VERSION 5.8 ;
BUSBITCHARS "[]" ;
DIVIDERCHAR "/" ;
UNITS
    DATABASE MICRONS 1000 ;
END UNITS

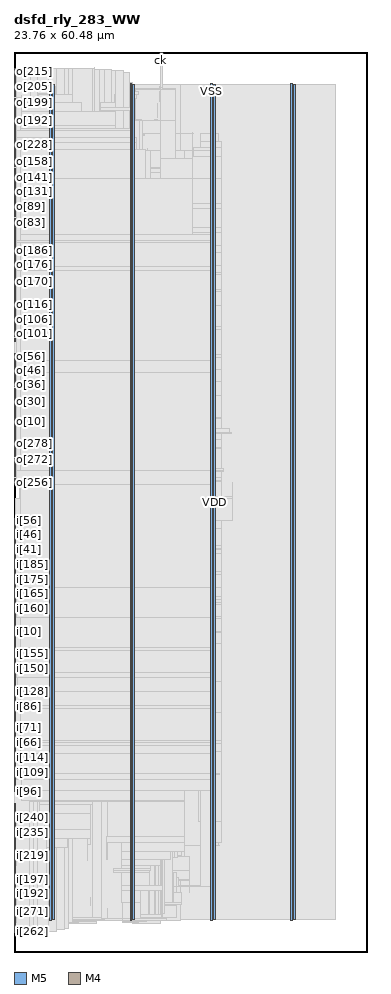
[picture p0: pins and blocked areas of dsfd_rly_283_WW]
MACRO dsfd_rly_283_WW
  FOREIGN dsfd_rly_283_WW 0 0 ;
  CLASS BLOCK ;
  SIZE 23.76 BY 60.48 ;
  PIN ck
    DIRECTION INPUT ;
    USE SIGNAL ;
    PORT
      LAYER M5 ;
        RECT  9.84 60.396 9.864 60.48 ;
    END
  END ck
  PIN i[0]
    DIRECTION INPUT ;
    USE SIGNAL ;
    PORT
      LAYER M4 ;
        RECT  0 20.016 0.084 20.04 ;
    END
  END i[0]
  PIN i[100]
    DIRECTION INPUT ;
    USE SIGNAL ;
    PORT
      LAYER M4 ;
        RECT  0 11.184 0.084 11.208 ;
    END
  END i[100]
  PIN i[101]
    DIRECTION INPUT ;
    USE SIGNAL ;
    PORT
      LAYER M4 ;
        RECT  0 11.28 0.084 11.304 ;
    END
  END i[101]
  PIN i[102]
    DIRECTION INPUT ;
    USE SIGNAL ;
    PORT
      LAYER M4 ;
        RECT  0 11.376 0.084 11.4 ;
    END
  END i[102]
  PIN i[103]
    DIRECTION INPUT ;
    USE SIGNAL ;
    PORT
      LAYER M4 ;
        RECT  0 11.472 0.084 11.496 ;
    END
  END i[103]
  PIN i[104]
    DIRECTION INPUT ;
    USE SIGNAL ;
    PORT
      LAYER M4 ;
        RECT  0 11.568 0.084 11.592 ;
    END
  END i[104]
  PIN i[105]
    DIRECTION INPUT ;
    USE SIGNAL ;
    PORT
      LAYER M4 ;
        RECT  0 11.664 0.084 11.688 ;
    END
  END i[105]
  PIN i[106]
    DIRECTION INPUT ;
    USE SIGNAL ;
    PORT
      LAYER M4 ;
        RECT  0 11.76 0.084 11.784 ;
    END
  END i[106]
  PIN i[107]
    DIRECTION INPUT ;
    USE SIGNAL ;
    PORT
      LAYER M4 ;
        RECT  0 11.856 0.084 11.88 ;
    END
  END i[107]
  PIN i[108]
    DIRECTION INPUT ;
    USE SIGNAL ;
    PORT
      LAYER M4 ;
        RECT  0 11.952 0.084 11.976 ;
    END
  END i[108]
  PIN i[109]
    DIRECTION INPUT ;
    USE SIGNAL ;
    PORT
      LAYER M4 ;
        RECT  0 12.048 0.084 12.072 ;
    END
  END i[109]
  PIN i[10]
    DIRECTION INPUT ;
    USE SIGNAL ;
    PORT
      LAYER M4 ;
        RECT  0 20.976 0.084 21 ;
    END
  END i[10]
  PIN i[110]
    DIRECTION INPUT ;
    USE SIGNAL ;
    PORT
      LAYER M4 ;
        RECT  0 12.144 0.084 12.168 ;
    END
  END i[110]
  PIN i[111]
    DIRECTION INPUT ;
    USE SIGNAL ;
    PORT
      LAYER M4 ;
        RECT  0 12.24 0.084 12.264 ;
    END
  END i[111]
  PIN i[112]
    DIRECTION INPUT ;
    USE SIGNAL ;
    PORT
      LAYER M4 ;
        RECT  0 12.336 0.084 12.36 ;
    END
  END i[112]
  PIN i[113]
    DIRECTION INPUT ;
    USE SIGNAL ;
    PORT
      LAYER M4 ;
        RECT  0 12.432 0.084 12.456 ;
    END
  END i[113]
  PIN i[114]
    DIRECTION INPUT ;
    USE SIGNAL ;
    PORT
      LAYER M4 ;
        RECT  0 12.528 0.084 12.552 ;
    END
  END i[114]
  PIN i[115]
    DIRECTION INPUT ;
    USE SIGNAL ;
    PORT
      LAYER M4 ;
        RECT  0 12.624 0.084 12.648 ;
    END
  END i[115]
  PIN i[116]
    DIRECTION INPUT ;
    USE SIGNAL ;
    PORT
      LAYER M4 ;
        RECT  0 12.72 0.084 12.744 ;
    END
  END i[116]
  PIN i[117]
    DIRECTION INPUT ;
    USE SIGNAL ;
    PORT
      LAYER M4 ;
        RECT  0 12.816 0.084 12.84 ;
    END
  END i[117]
  PIN i[118]
    DIRECTION INPUT ;
    USE SIGNAL ;
    PORT
      LAYER M4 ;
        RECT  0 12.912 0.084 12.936 ;
    END
  END i[118]
  PIN i[119]
    DIRECTION INPUT ;
    USE SIGNAL ;
    PORT
      LAYER M4 ;
        RECT  0 13.008 0.084 13.032 ;
    END
  END i[119]
  PIN i[11]
    DIRECTION INPUT ;
    USE SIGNAL ;
    PORT
      LAYER M4 ;
        RECT  0 21.072 0.084 21.096 ;
    END
  END i[11]
  PIN i[120]
    DIRECTION INPUT ;
    USE SIGNAL ;
    PORT
      LAYER M4 ;
        RECT  0 13.104 0.084 13.128 ;
    END
  END i[120]
  PIN i[121]
    DIRECTION INPUT ;
    USE SIGNAL ;
    PORT
      LAYER M4 ;
        RECT  0 13.2 0.084 13.224 ;
    END
  END i[121]
  PIN i[122]
    DIRECTION INPUT ;
    USE SIGNAL ;
    PORT
      LAYER M4 ;
        RECT  0 13.296 0.084 13.32 ;
    END
  END i[122]
  PIN i[123]
    DIRECTION INPUT ;
    USE SIGNAL ;
    PORT
      LAYER M4 ;
        RECT  0 13.392 0.084 13.416 ;
    END
  END i[123]
  PIN i[124]
    DIRECTION INPUT ;
    USE SIGNAL ;
    PORT
      LAYER M4 ;
        RECT  0 13.488 0.084 13.512 ;
    END
  END i[124]
  PIN i[125]
    DIRECTION INPUT ;
    USE SIGNAL ;
    PORT
      LAYER M4 ;
        RECT  0 13.584 0.084 13.608 ;
    END
  END i[125]
  PIN i[126]
    DIRECTION INPUT ;
    USE SIGNAL ;
    PORT
      LAYER M4 ;
        RECT  0 13.68 0.084 13.704 ;
    END
  END i[126]
  PIN i[127]
    DIRECTION INPUT ;
    USE SIGNAL ;
    PORT
      LAYER M4 ;
        RECT  0 13.776 0.084 13.8 ;
    END
  END i[127]
  PIN i[128]
    DIRECTION INPUT ;
    USE SIGNAL ;
    PORT
      LAYER M4 ;
        RECT  0 16.944 0.084 16.968 ;
    END
  END i[128]
  PIN i[129]
    DIRECTION INPUT ;
    USE SIGNAL ;
    PORT
      LAYER M4 ;
        RECT  0 17.04 0.084 17.064 ;
    END
  END i[129]
  PIN i[12]
    DIRECTION INPUT ;
    USE SIGNAL ;
    PORT
      LAYER M4 ;
        RECT  0 21.168 0.084 21.192 ;
    END
  END i[12]
  PIN i[130]
    DIRECTION INPUT ;
    USE SIGNAL ;
    PORT
      LAYER M4 ;
        RECT  0 17.136 0.084 17.16 ;
    END
  END i[130]
  PIN i[131]
    DIRECTION INPUT ;
    USE SIGNAL ;
    PORT
      LAYER M4 ;
        RECT  0 17.232 0.084 17.256 ;
    END
  END i[131]
  PIN i[132]
    DIRECTION INPUT ;
    USE SIGNAL ;
    PORT
      LAYER M4 ;
        RECT  0 17.328 0.084 17.352 ;
    END
  END i[132]
  PIN i[133]
    DIRECTION INPUT ;
    USE SIGNAL ;
    PORT
      LAYER M4 ;
        RECT  0 17.424 0.084 17.448 ;
    END
  END i[133]
  PIN i[134]
    DIRECTION INPUT ;
    USE SIGNAL ;
    PORT
      LAYER M4 ;
        RECT  0 17.52 0.084 17.544 ;
    END
  END i[134]
  PIN i[135]
    DIRECTION INPUT ;
    USE SIGNAL ;
    PORT
      LAYER M4 ;
        RECT  0 17.616 0.084 17.64 ;
    END
  END i[135]
  PIN i[136]
    DIRECTION INPUT ;
    USE SIGNAL ;
    PORT
      LAYER M4 ;
        RECT  0 17.712 0.084 17.736 ;
    END
  END i[136]
  PIN i[137]
    DIRECTION INPUT ;
    USE SIGNAL ;
    PORT
      LAYER M4 ;
        RECT  0 17.808 0.084 17.832 ;
    END
  END i[137]
  PIN i[138]
    DIRECTION INPUT ;
    USE SIGNAL ;
    PORT
      LAYER M4 ;
        RECT  0 17.904 0.084 17.928 ;
    END
  END i[138]
  PIN i[139]
    DIRECTION INPUT ;
    USE SIGNAL ;
    PORT
      LAYER M4 ;
        RECT  0 18 0.084 18.024 ;
    END
  END i[139]
  PIN i[13]
    DIRECTION INPUT ;
    USE SIGNAL ;
    PORT
      LAYER M4 ;
        RECT  0 21.264 0.084 21.288 ;
    END
  END i[13]
  PIN i[140]
    DIRECTION INPUT ;
    USE SIGNAL ;
    PORT
      LAYER M4 ;
        RECT  0 18.096 0.084 18.12 ;
    END
  END i[140]
  PIN i[141]
    DIRECTION INPUT ;
    USE SIGNAL ;
    PORT
      LAYER M4 ;
        RECT  0 18.192 0.084 18.216 ;
    END
  END i[141]
  PIN i[142]
    DIRECTION INPUT ;
    USE SIGNAL ;
    PORT
      LAYER M4 ;
        RECT  0 18.288 0.084 18.312 ;
    END
  END i[142]
  PIN i[143]
    DIRECTION INPUT ;
    USE SIGNAL ;
    PORT
      LAYER M4 ;
        RECT  0 18.384 0.084 18.408 ;
    END
  END i[143]
  PIN i[144]
    DIRECTION INPUT ;
    USE SIGNAL ;
    PORT
      LAYER M4 ;
        RECT  0 18.48 0.084 18.504 ;
    END
  END i[144]
  PIN i[145]
    DIRECTION INPUT ;
    USE SIGNAL ;
    PORT
      LAYER M4 ;
        RECT  0 18.576 0.084 18.6 ;
    END
  END i[145]
  PIN i[146]
    DIRECTION INPUT ;
    USE SIGNAL ;
    PORT
      LAYER M4 ;
        RECT  0 18.672 0.084 18.696 ;
    END
  END i[146]
  PIN i[147]
    DIRECTION INPUT ;
    USE SIGNAL ;
    PORT
      LAYER M4 ;
        RECT  0 18.768 0.084 18.792 ;
    END
  END i[147]
  PIN i[148]
    DIRECTION INPUT ;
    USE SIGNAL ;
    PORT
      LAYER M4 ;
        RECT  0 18.864 0.084 18.888 ;
    END
  END i[148]
  PIN i[149]
    DIRECTION INPUT ;
    USE SIGNAL ;
    PORT
      LAYER M4 ;
        RECT  0 18.96 0.084 18.984 ;
    END
  END i[149]
  PIN i[14]
    DIRECTION INPUT ;
    USE SIGNAL ;
    PORT
      LAYER M4 ;
        RECT  0 21.36 0.084 21.384 ;
    END
  END i[14]
  PIN i[150]
    DIRECTION INPUT ;
    USE SIGNAL ;
    PORT
      LAYER M4 ;
        RECT  0 19.056 0.084 19.08 ;
    END
  END i[150]
  PIN i[151]
    DIRECTION INPUT ;
    USE SIGNAL ;
    PORT
      LAYER M4 ;
        RECT  0 19.152 0.084 19.176 ;
    END
  END i[151]
  PIN i[152]
    DIRECTION INPUT ;
    USE SIGNAL ;
    PORT
      LAYER M4 ;
        RECT  0 19.248 0.084 19.272 ;
    END
  END i[152]
  PIN i[153]
    DIRECTION INPUT ;
    USE SIGNAL ;
    PORT
      LAYER M4 ;
        RECT  0 19.344 0.084 19.368 ;
    END
  END i[153]
  PIN i[154]
    DIRECTION INPUT ;
    USE SIGNAL ;
    PORT
      LAYER M4 ;
        RECT  0 19.44 0.084 19.464 ;
    END
  END i[154]
  PIN i[155]
    DIRECTION INPUT ;
    USE SIGNAL ;
    PORT
      LAYER M4 ;
        RECT  0 19.536 0.084 19.56 ;
    END
  END i[155]
  PIN i[156]
    DIRECTION INPUT ;
    USE SIGNAL ;
    PORT
      LAYER M4 ;
        RECT  0 19.632 0.084 19.656 ;
    END
  END i[156]
  PIN i[157]
    DIRECTION INPUT ;
    USE SIGNAL ;
    PORT
      LAYER M4 ;
        RECT  0 19.728 0.084 19.752 ;
    END
  END i[157]
  PIN i[158]
    DIRECTION INPUT ;
    USE SIGNAL ;
    PORT
      LAYER M4 ;
        RECT  0 19.824 0.084 19.848 ;
    END
  END i[158]
  PIN i[159]
    DIRECTION INPUT ;
    USE SIGNAL ;
    PORT
      LAYER M4 ;
        RECT  0 19.92 0.084 19.944 ;
    END
  END i[159]
  PIN i[15]
    DIRECTION INPUT ;
    USE SIGNAL ;
    PORT
      LAYER M4 ;
        RECT  0 21.456 0.084 21.48 ;
    END
  END i[15]
  PIN i[160]
    DIRECTION INPUT ;
    USE SIGNAL ;
    PORT
      LAYER M4 ;
        RECT  0 23.088 0.084 23.112 ;
    END
  END i[160]
  PIN i[161]
    DIRECTION INPUT ;
    USE SIGNAL ;
    PORT
      LAYER M4 ;
        RECT  0 23.184 0.084 23.208 ;
    END
  END i[161]
  PIN i[162]
    DIRECTION INPUT ;
    USE SIGNAL ;
    PORT
      LAYER M4 ;
        RECT  0 23.28 0.084 23.304 ;
    END
  END i[162]
  PIN i[163]
    DIRECTION INPUT ;
    USE SIGNAL ;
    PORT
      LAYER M4 ;
        RECT  0 23.376 0.084 23.4 ;
    END
  END i[163]
  PIN i[164]
    DIRECTION INPUT ;
    USE SIGNAL ;
    PORT
      LAYER M4 ;
        RECT  0 23.472 0.084 23.496 ;
    END
  END i[164]
  PIN i[165]
    DIRECTION INPUT ;
    USE SIGNAL ;
    PORT
      LAYER M4 ;
        RECT  0 23.568 0.084 23.592 ;
    END
  END i[165]
  PIN i[166]
    DIRECTION INPUT ;
    USE SIGNAL ;
    PORT
      LAYER M4 ;
        RECT  0 23.664 0.084 23.688 ;
    END
  END i[166]
  PIN i[167]
    DIRECTION INPUT ;
    USE SIGNAL ;
    PORT
      LAYER M4 ;
        RECT  0 23.76 0.084 23.784 ;
    END
  END i[167]
  PIN i[168]
    DIRECTION INPUT ;
    USE SIGNAL ;
    PORT
      LAYER M4 ;
        RECT  0 23.856 0.084 23.88 ;
    END
  END i[168]
  PIN i[169]
    DIRECTION INPUT ;
    USE SIGNAL ;
    PORT
      LAYER M4 ;
        RECT  0 23.952 0.084 23.976 ;
    END
  END i[169]
  PIN i[16]
    DIRECTION INPUT ;
    USE SIGNAL ;
    PORT
      LAYER M4 ;
        RECT  0 21.552 0.084 21.576 ;
    END
  END i[16]
  PIN i[170]
    DIRECTION INPUT ;
    USE SIGNAL ;
    PORT
      LAYER M4 ;
        RECT  0 24.048 0.084 24.072 ;
    END
  END i[170]
  PIN i[171]
    DIRECTION INPUT ;
    USE SIGNAL ;
    PORT
      LAYER M4 ;
        RECT  0 24.144 0.084 24.168 ;
    END
  END i[171]
  PIN i[172]
    DIRECTION INPUT ;
    USE SIGNAL ;
    PORT
      LAYER M4 ;
        RECT  0 24.24 0.084 24.264 ;
    END
  END i[172]
  PIN i[173]
    DIRECTION INPUT ;
    USE SIGNAL ;
    PORT
      LAYER M4 ;
        RECT  0 24.336 0.084 24.36 ;
    END
  END i[173]
  PIN i[174]
    DIRECTION INPUT ;
    USE SIGNAL ;
    PORT
      LAYER M4 ;
        RECT  0 24.432 0.084 24.456 ;
    END
  END i[174]
  PIN i[175]
    DIRECTION INPUT ;
    USE SIGNAL ;
    PORT
      LAYER M4 ;
        RECT  0 24.528 0.084 24.552 ;
    END
  END i[175]
  PIN i[176]
    DIRECTION INPUT ;
    USE SIGNAL ;
    PORT
      LAYER M4 ;
        RECT  0 24.624 0.084 24.648 ;
    END
  END i[176]
  PIN i[177]
    DIRECTION INPUT ;
    USE SIGNAL ;
    PORT
      LAYER M4 ;
        RECT  0 24.72 0.084 24.744 ;
    END
  END i[177]
  PIN i[178]
    DIRECTION INPUT ;
    USE SIGNAL ;
    PORT
      LAYER M4 ;
        RECT  0 24.816 0.084 24.84 ;
    END
  END i[178]
  PIN i[179]
    DIRECTION INPUT ;
    USE SIGNAL ;
    PORT
      LAYER M4 ;
        RECT  0 24.912 0.084 24.936 ;
    END
  END i[179]
  PIN i[17]
    DIRECTION INPUT ;
    USE SIGNAL ;
    PORT
      LAYER M4 ;
        RECT  0 21.648 0.084 21.672 ;
    END
  END i[17]
  PIN i[180]
    DIRECTION INPUT ;
    USE SIGNAL ;
    PORT
      LAYER M4 ;
        RECT  0 25.008 0.084 25.032 ;
    END
  END i[180]
  PIN i[181]
    DIRECTION INPUT ;
    USE SIGNAL ;
    PORT
      LAYER M4 ;
        RECT  0 25.104 0.084 25.128 ;
    END
  END i[181]
  PIN i[182]
    DIRECTION INPUT ;
    USE SIGNAL ;
    PORT
      LAYER M4 ;
        RECT  0 25.2 0.084 25.224 ;
    END
  END i[182]
  PIN i[183]
    DIRECTION INPUT ;
    USE SIGNAL ;
    PORT
      LAYER M4 ;
        RECT  0 25.296 0.084 25.32 ;
    END
  END i[183]
  PIN i[184]
    DIRECTION INPUT ;
    USE SIGNAL ;
    PORT
      LAYER M4 ;
        RECT  0 25.392 0.084 25.416 ;
    END
  END i[184]
  PIN i[185]
    DIRECTION INPUT ;
    USE SIGNAL ;
    PORT
      LAYER M4 ;
        RECT  0 25.488 0.084 25.512 ;
    END
  END i[185]
  PIN i[186]
    DIRECTION INPUT ;
    USE SIGNAL ;
    PORT
      LAYER M4 ;
        RECT  0 25.584 0.084 25.608 ;
    END
  END i[186]
  PIN i[187]
    DIRECTION INPUT ;
    USE SIGNAL ;
    PORT
      LAYER M4 ;
        RECT  0 25.68 0.084 25.704 ;
    END
  END i[187]
  PIN i[188]
    DIRECTION INPUT ;
    USE SIGNAL ;
    PORT
      LAYER M4 ;
        RECT  0 25.776 0.084 25.8 ;
    END
  END i[188]
  PIN i[189]
    DIRECTION INPUT ;
    USE SIGNAL ;
    PORT
      LAYER M4 ;
        RECT  0 25.872 0.084 25.896 ;
    END
  END i[189]
  PIN i[18]
    DIRECTION INPUT ;
    USE SIGNAL ;
    PORT
      LAYER M4 ;
        RECT  0 21.744 0.084 21.768 ;
    END
  END i[18]
  PIN i[190]
    DIRECTION INPUT ;
    USE SIGNAL ;
    PORT
      LAYER M4 ;
        RECT  0 25.968 0.084 25.992 ;
    END
  END i[190]
  PIN i[191]
    DIRECTION INPUT ;
    USE SIGNAL ;
    PORT
      LAYER M4 ;
        RECT  0 26.064 0.084 26.088 ;
    END
  END i[191]
  PIN i[192]
    DIRECTION INPUT ;
    USE SIGNAL ;
    PORT
      LAYER M4 ;
        RECT  0 3.888 0.084 3.912 ;
    END
  END i[192]
  PIN i[193]
    DIRECTION INPUT ;
    USE SIGNAL ;
    PORT
      LAYER M4 ;
        RECT  0 3.984 0.084 4.008 ;
    END
  END i[193]
  PIN i[194]
    DIRECTION INPUT ;
    USE SIGNAL ;
    PORT
      LAYER M4 ;
        RECT  0 4.08 0.084 4.104 ;
    END
  END i[194]
  PIN i[195]
    DIRECTION INPUT ;
    USE SIGNAL ;
    PORT
      LAYER M4 ;
        RECT  0 4.176 0.084 4.2 ;
    END
  END i[195]
  PIN i[196]
    DIRECTION INPUT ;
    USE SIGNAL ;
    PORT
      LAYER M4 ;
        RECT  0 4.272 0.084 4.296 ;
    END
  END i[196]
  PIN i[197]
    DIRECTION INPUT ;
    USE SIGNAL ;
    PORT
      LAYER M4 ;
        RECT  0 4.368 0.084 4.392 ;
    END
  END i[197]
  PIN i[198]
    DIRECTION INPUT ;
    USE SIGNAL ;
    PORT
      LAYER M4 ;
        RECT  0 4.464 0.084 4.488 ;
    END
  END i[198]
  PIN i[199]
    DIRECTION INPUT ;
    USE SIGNAL ;
    PORT
      LAYER M4 ;
        RECT  0 4.56 0.084 4.584 ;
    END
  END i[199]
  PIN i[19]
    DIRECTION INPUT ;
    USE SIGNAL ;
    PORT
      LAYER M4 ;
        RECT  0 21.84 0.084 21.864 ;
    END
  END i[19]
  PIN i[1]
    DIRECTION INPUT ;
    USE SIGNAL ;
    PORT
      LAYER M4 ;
        RECT  0 20.112 0.084 20.136 ;
    END
  END i[1]
  PIN i[200]
    DIRECTION INPUT ;
    USE SIGNAL ;
    PORT
      LAYER M4 ;
        RECT  0 4.656 0.084 4.68 ;
    END
  END i[200]
  PIN i[201]
    DIRECTION INPUT ;
    USE SIGNAL ;
    PORT
      LAYER M4 ;
        RECT  0 4.752 0.084 4.776 ;
    END
  END i[201]
  PIN i[202]
    DIRECTION INPUT ;
    USE SIGNAL ;
    PORT
      LAYER M4 ;
        RECT  0 4.848 0.084 4.872 ;
    END
  END i[202]
  PIN i[203]
    DIRECTION INPUT ;
    USE SIGNAL ;
    PORT
      LAYER M4 ;
        RECT  0 4.944 0.084 4.968 ;
    END
  END i[203]
  PIN i[204]
    DIRECTION INPUT ;
    USE SIGNAL ;
    PORT
      LAYER M4 ;
        RECT  0 5.04 0.084 5.064 ;
    END
  END i[204]
  PIN i[205]
    DIRECTION INPUT ;
    USE SIGNAL ;
    PORT
      LAYER M4 ;
        RECT  0 5.136 0.084 5.16 ;
    END
  END i[205]
  PIN i[206]
    DIRECTION INPUT ;
    USE SIGNAL ;
    PORT
      LAYER M4 ;
        RECT  0 5.232 0.084 5.256 ;
    END
  END i[206]
  PIN i[207]
    DIRECTION INPUT ;
    USE SIGNAL ;
    PORT
      LAYER M4 ;
        RECT  0 5.328 0.084 5.352 ;
    END
  END i[207]
  PIN i[208]
    DIRECTION INPUT ;
    USE SIGNAL ;
    PORT
      LAYER M4 ;
        RECT  0 5.424 0.084 5.448 ;
    END
  END i[208]
  PIN i[209]
    DIRECTION INPUT ;
    USE SIGNAL ;
    PORT
      LAYER M4 ;
        RECT  0 5.52 0.084 5.544 ;
    END
  END i[209]
  PIN i[20]
    DIRECTION INPUT ;
    USE SIGNAL ;
    PORT
      LAYER M4 ;
        RECT  0 21.936 0.084 21.96 ;
    END
  END i[20]
  PIN i[210]
    DIRECTION INPUT ;
    USE SIGNAL ;
    PORT
      LAYER M4 ;
        RECT  0 5.616 0.084 5.64 ;
    END
  END i[210]
  PIN i[211]
    DIRECTION INPUT ;
    USE SIGNAL ;
    PORT
      LAYER M4 ;
        RECT  0 5.712 0.084 5.736 ;
    END
  END i[211]
  PIN i[212]
    DIRECTION INPUT ;
    USE SIGNAL ;
    PORT
      LAYER M4 ;
        RECT  0 5.808 0.084 5.832 ;
    END
  END i[212]
  PIN i[213]
    DIRECTION INPUT ;
    USE SIGNAL ;
    PORT
      LAYER M4 ;
        RECT  0 5.904 0.084 5.928 ;
    END
  END i[213]
  PIN i[214]
    DIRECTION INPUT ;
    USE SIGNAL ;
    PORT
      LAYER M4 ;
        RECT  0 6 0.084 6.024 ;
    END
  END i[214]
  PIN i[215]
    DIRECTION INPUT ;
    USE SIGNAL ;
    PORT
      LAYER M4 ;
        RECT  0 6.096 0.084 6.12 ;
    END
  END i[215]
  PIN i[216]
    DIRECTION INPUT ;
    USE SIGNAL ;
    PORT
      LAYER M4 ;
        RECT  0 6.192 0.084 6.216 ;
    END
  END i[216]
  PIN i[217]
    DIRECTION INPUT ;
    USE SIGNAL ;
    PORT
      LAYER M4 ;
        RECT  0 6.288 0.084 6.312 ;
    END
  END i[217]
  PIN i[218]
    DIRECTION INPUT ;
    USE SIGNAL ;
    PORT
      LAYER M4 ;
        RECT  0 6.384 0.084 6.408 ;
    END
  END i[218]
  PIN i[219]
    DIRECTION INPUT ;
    USE SIGNAL ;
    PORT
      LAYER M4 ;
        RECT  0 6.48 0.084 6.504 ;
    END
  END i[219]
  PIN i[21]
    DIRECTION INPUT ;
    USE SIGNAL ;
    PORT
      LAYER M4 ;
        RECT  0 22.032 0.084 22.056 ;
    END
  END i[21]
  PIN i[220]
    DIRECTION INPUT ;
    USE SIGNAL ;
    PORT
      LAYER M4 ;
        RECT  0 6.576 0.084 6.6 ;
    END
  END i[220]
  PIN i[221]
    DIRECTION INPUT ;
    USE SIGNAL ;
    PORT
      LAYER M4 ;
        RECT  0 6.672 0.084 6.696 ;
    END
  END i[221]
  PIN i[222]
    DIRECTION INPUT ;
    USE SIGNAL ;
    PORT
      LAYER M4 ;
        RECT  0 6.768 0.084 6.792 ;
    END
  END i[222]
  PIN i[223]
    DIRECTION INPUT ;
    USE SIGNAL ;
    PORT
      LAYER M4 ;
        RECT  0 6.864 0.084 6.888 ;
    END
  END i[223]
  PIN i[224]
    DIRECTION INPUT ;
    USE SIGNAL ;
    PORT
      LAYER M4 ;
        RECT  0 6.96 0.084 6.984 ;
    END
  END i[224]
  PIN i[225]
    DIRECTION INPUT ;
    USE SIGNAL ;
    PORT
      LAYER M4 ;
        RECT  0 7.056 0.084 7.08 ;
    END
  END i[225]
  PIN i[226]
    DIRECTION INPUT ;
    USE SIGNAL ;
    PORT
      LAYER M4 ;
        RECT  0 7.152 0.084 7.176 ;
    END
  END i[226]
  PIN i[227]
    DIRECTION INPUT ;
    USE SIGNAL ;
    PORT
      LAYER M4 ;
        RECT  0 7.248 0.084 7.272 ;
    END
  END i[227]
  PIN i[228]
    DIRECTION INPUT ;
    USE SIGNAL ;
    PORT
      LAYER M4 ;
        RECT  0 7.344 0.084 7.368 ;
    END
  END i[228]
  PIN i[229]
    DIRECTION INPUT ;
    USE SIGNAL ;
    PORT
      LAYER M4 ;
        RECT  0 7.44 0.084 7.464 ;
    END
  END i[229]
  PIN i[22]
    DIRECTION INPUT ;
    USE SIGNAL ;
    PORT
      LAYER M4 ;
        RECT  0 22.128 0.084 22.152 ;
    END
  END i[22]
  PIN i[230]
    DIRECTION INPUT ;
    USE SIGNAL ;
    PORT
      LAYER M4 ;
        RECT  0 7.536 0.084 7.56 ;
    END
  END i[230]
  PIN i[231]
    DIRECTION INPUT ;
    USE SIGNAL ;
    PORT
      LAYER M4 ;
        RECT  0 7.632 0.084 7.656 ;
    END
  END i[231]
  PIN i[232]
    DIRECTION INPUT ;
    USE SIGNAL ;
    PORT
      LAYER M4 ;
        RECT  0 7.728 0.084 7.752 ;
    END
  END i[232]
  PIN i[233]
    DIRECTION INPUT ;
    USE SIGNAL ;
    PORT
      LAYER M4 ;
        RECT  0 7.824 0.084 7.848 ;
    END
  END i[233]
  PIN i[234]
    DIRECTION INPUT ;
    USE SIGNAL ;
    PORT
      LAYER M4 ;
        RECT  0 7.92 0.084 7.944 ;
    END
  END i[234]
  PIN i[235]
    DIRECTION INPUT ;
    USE SIGNAL ;
    PORT
      LAYER M4 ;
        RECT  0 8.016 0.084 8.04 ;
    END
  END i[235]
  PIN i[236]
    DIRECTION INPUT ;
    USE SIGNAL ;
    PORT
      LAYER M4 ;
        RECT  0 8.112 0.084 8.136 ;
    END
  END i[236]
  PIN i[237]
    DIRECTION INPUT ;
    USE SIGNAL ;
    PORT
      LAYER M4 ;
        RECT  0 8.208 0.084 8.232 ;
    END
  END i[237]
  PIN i[238]
    DIRECTION INPUT ;
    USE SIGNAL ;
    PORT
      LAYER M4 ;
        RECT  0 8.304 0.084 8.328 ;
    END
  END i[238]
  PIN i[239]
    DIRECTION INPUT ;
    USE SIGNAL ;
    PORT
      LAYER M4 ;
        RECT  0 8.4 0.084 8.424 ;
    END
  END i[239]
  PIN i[23]
    DIRECTION INPUT ;
    USE SIGNAL ;
    PORT
      LAYER M4 ;
        RECT  0 22.224 0.084 22.248 ;
    END
  END i[23]
  PIN i[240]
    DIRECTION INPUT ;
    USE SIGNAL ;
    PORT
      LAYER M4 ;
        RECT  0 8.496 0.084 8.52 ;
    END
  END i[240]
  PIN i[241]
    DIRECTION INPUT ;
    USE SIGNAL ;
    PORT
      LAYER M4 ;
        RECT  0 8.592 0.084 8.616 ;
    END
  END i[241]
  PIN i[242]
    DIRECTION INPUT ;
    USE SIGNAL ;
    PORT
      LAYER M4 ;
        RECT  0 8.688 0.084 8.712 ;
    END
  END i[242]
  PIN i[243]
    DIRECTION INPUT ;
    USE SIGNAL ;
    PORT
      LAYER M4 ;
        RECT  0 8.784 0.084 8.808 ;
    END
  END i[243]
  PIN i[244]
    DIRECTION INPUT ;
    USE SIGNAL ;
    PORT
      LAYER M4 ;
        RECT  0 8.88 0.084 8.904 ;
    END
  END i[244]
  PIN i[245]
    DIRECTION INPUT ;
    USE SIGNAL ;
    PORT
      LAYER M4 ;
        RECT  0 8.976 0.084 9 ;
    END
  END i[245]
  PIN i[246]
    DIRECTION INPUT ;
    USE SIGNAL ;
    PORT
      LAYER M4 ;
        RECT  0 9.072 0.084 9.096 ;
    END
  END i[246]
  PIN i[247]
    DIRECTION INPUT ;
    USE SIGNAL ;
    PORT
      LAYER M4 ;
        RECT  0 9.168 0.084 9.192 ;
    END
  END i[247]
  PIN i[248]
    DIRECTION INPUT ;
    USE SIGNAL ;
    PORT
      LAYER M4 ;
        RECT  0 9.264 0.084 9.288 ;
    END
  END i[248]
  PIN i[249]
    DIRECTION INPUT ;
    USE SIGNAL ;
    PORT
      LAYER M4 ;
        RECT  0 9.36 0.084 9.384 ;
    END
  END i[249]
  PIN i[24]
    DIRECTION INPUT ;
    USE SIGNAL ;
    PORT
      LAYER M4 ;
        RECT  0 22.32 0.084 22.344 ;
    END
  END i[24]
  PIN i[250]
    DIRECTION INPUT ;
    USE SIGNAL ;
    PORT
      LAYER M4 ;
        RECT  0 9.456 0.084 9.48 ;
    END
  END i[250]
  PIN i[251]
    DIRECTION INPUT ;
    USE SIGNAL ;
    PORT
      LAYER M4 ;
        RECT  0 9.552 0.084 9.576 ;
    END
  END i[251]
  PIN i[252]
    DIRECTION INPUT ;
    USE SIGNAL ;
    PORT
      LAYER M4 ;
        RECT  0 9.648 0.084 9.672 ;
    END
  END i[252]
  PIN i[253]
    DIRECTION INPUT ;
    USE SIGNAL ;
    PORT
      LAYER M4 ;
        RECT  0 9.744 0.084 9.768 ;
    END
  END i[253]
  PIN i[254]
    DIRECTION INPUT ;
    USE SIGNAL ;
    PORT
      LAYER M4 ;
        RECT  0 9.84 0.084 9.864 ;
    END
  END i[254]
  PIN i[255]
    DIRECTION INPUT ;
    USE SIGNAL ;
    PORT
      LAYER M4 ;
        RECT  0 9.936 0.084 9.96 ;
    END
  END i[255]
  PIN i[256]
    DIRECTION INPUT ;
    USE SIGNAL ;
    PORT
      LAYER M4 ;
        RECT  0 1.296 0.084 1.32 ;
    END
  END i[256]
  PIN i[257]
    DIRECTION INPUT ;
    USE SIGNAL ;
    PORT
      LAYER M4 ;
        RECT  0 1.392 0.084 1.416 ;
    END
  END i[257]
  PIN i[258]
    DIRECTION INPUT ;
    USE SIGNAL ;
    PORT
      LAYER M4 ;
        RECT  0 1.488 0.084 1.512 ;
    END
  END i[258]
  PIN i[259]
    DIRECTION INPUT ;
    USE SIGNAL ;
    PORT
      LAYER M4 ;
        RECT  0 1.584 0.084 1.608 ;
    END
  END i[259]
  PIN i[25]
    DIRECTION INPUT ;
    USE SIGNAL ;
    PORT
      LAYER M4 ;
        RECT  0 22.416 0.084 22.44 ;
    END
  END i[25]
  PIN i[260]
    DIRECTION INPUT ;
    USE SIGNAL ;
    PORT
      LAYER M4 ;
        RECT  0 1.68 0.084 1.704 ;
    END
  END i[260]
  PIN i[261]
    DIRECTION INPUT ;
    USE SIGNAL ;
    PORT
      LAYER M4 ;
        RECT  0 1.776 0.084 1.8 ;
    END
  END i[261]
  PIN i[262]
    DIRECTION INPUT ;
    USE SIGNAL ;
    PORT
      LAYER M4 ;
        RECT  0 1.872 0.084 1.896 ;
    END
  END i[262]
  PIN i[263]
    DIRECTION INPUT ;
    USE SIGNAL ;
    PORT
      LAYER M4 ;
        RECT  0 1.968 0.084 1.992 ;
    END
  END i[263]
  PIN i[264]
    DIRECTION INPUT ;
    USE SIGNAL ;
    PORT
      LAYER M4 ;
        RECT  0 2.064 0.084 2.088 ;
    END
  END i[264]
  PIN i[265]
    DIRECTION INPUT ;
    USE SIGNAL ;
    PORT
      LAYER M4 ;
        RECT  0 2.16 0.084 2.184 ;
    END
  END i[265]
  PIN i[266]
    DIRECTION INPUT ;
    USE SIGNAL ;
    PORT
      LAYER M4 ;
        RECT  0 2.256 0.084 2.28 ;
    END
  END i[266]
  PIN i[267]
    DIRECTION INPUT ;
    USE SIGNAL ;
    PORT
      LAYER M4 ;
        RECT  0 2.352 0.084 2.376 ;
    END
  END i[267]
  PIN i[268]
    DIRECTION INPUT ;
    USE SIGNAL ;
    PORT
      LAYER M4 ;
        RECT  0 2.448 0.084 2.472 ;
    END
  END i[268]
  PIN i[269]
    DIRECTION INPUT ;
    USE SIGNAL ;
    PORT
      LAYER M4 ;
        RECT  0 2.544 0.084 2.568 ;
    END
  END i[269]
  PIN i[26]
    DIRECTION INPUT ;
    USE SIGNAL ;
    PORT
      LAYER M4 ;
        RECT  0 22.512 0.084 22.536 ;
    END
  END i[26]
  PIN i[270]
    DIRECTION INPUT ;
    USE SIGNAL ;
    PORT
      LAYER M4 ;
        RECT  0 2.64 0.084 2.664 ;
    END
  END i[270]
  PIN i[271]
    DIRECTION INPUT ;
    USE SIGNAL ;
    PORT
      LAYER M4 ;
        RECT  0 2.736 0.084 2.76 ;
    END
  END i[271]
  PIN i[272]
    DIRECTION INPUT ;
    USE SIGNAL ;
    PORT
      LAYER M4 ;
        RECT  0 2.832 0.084 2.856 ;
    END
  END i[272]
  PIN i[273]
    DIRECTION INPUT ;
    USE SIGNAL ;
    PORT
      LAYER M4 ;
        RECT  0 2.928 0.084 2.952 ;
    END
  END i[273]
  PIN i[274]
    DIRECTION INPUT ;
    USE SIGNAL ;
    PORT
      LAYER M4 ;
        RECT  0 3.024 0.084 3.048 ;
    END
  END i[274]
  PIN i[275]
    DIRECTION INPUT ;
    USE SIGNAL ;
    PORT
      LAYER M4 ;
        RECT  0 3.12 0.084 3.144 ;
    END
  END i[275]
  PIN i[276]
    DIRECTION INPUT ;
    USE SIGNAL ;
    PORT
      LAYER M4 ;
        RECT  0 3.216 0.084 3.24 ;
    END
  END i[276]
  PIN i[277]
    DIRECTION INPUT ;
    USE SIGNAL ;
    PORT
      LAYER M4 ;
        RECT  0 3.312 0.084 3.336 ;
    END
  END i[277]
  PIN i[278]
    DIRECTION INPUT ;
    USE SIGNAL ;
    PORT
      LAYER M4 ;
        RECT  0 3.408 0.084 3.432 ;
    END
  END i[278]
  PIN i[279]
    DIRECTION INPUT ;
    USE SIGNAL ;
    PORT
      LAYER M4 ;
        RECT  0 3.504 0.084 3.528 ;
    END
  END i[279]
  PIN i[27]
    DIRECTION INPUT ;
    USE SIGNAL ;
    PORT
      LAYER M4 ;
        RECT  0 22.608 0.084 22.632 ;
    END
  END i[27]
  PIN i[280]
    DIRECTION INPUT ;
    USE SIGNAL ;
    PORT
      LAYER M4 ;
        RECT  0 3.6 0.084 3.624 ;
    END
  END i[280]
  PIN i[281]
    DIRECTION INPUT ;
    USE SIGNAL ;
    PORT
      LAYER M4 ;
        RECT  0 3.696 0.084 3.72 ;
    END
  END i[281]
  PIN i[282]
    DIRECTION INPUT ;
    USE SIGNAL ;
    PORT
      LAYER M4 ;
        RECT  0 3.792 0.084 3.816 ;
    END
  END i[282]
  PIN i[28]
    DIRECTION INPUT ;
    USE SIGNAL ;
    PORT
      LAYER M4 ;
        RECT  0 22.704 0.084 22.728 ;
    END
  END i[28]
  PIN i[29]
    DIRECTION INPUT ;
    USE SIGNAL ;
    PORT
      LAYER M4 ;
        RECT  0 22.8 0.084 22.824 ;
    END
  END i[29]
  PIN i[2]
    DIRECTION INPUT ;
    USE SIGNAL ;
    PORT
      LAYER M4 ;
        RECT  0 20.208 0.084 20.232 ;
    END
  END i[2]
  PIN i[30]
    DIRECTION INPUT ;
    USE SIGNAL ;
    PORT
      LAYER M4 ;
        RECT  0 22.896 0.084 22.92 ;
    END
  END i[30]
  PIN i[31]
    DIRECTION INPUT ;
    USE SIGNAL ;
    PORT
      LAYER M4 ;
        RECT  0 22.992 0.084 23.016 ;
    END
  END i[31]
  PIN i[32]
    DIRECTION INPUT ;
    USE SIGNAL ;
    PORT
      LAYER M4 ;
        RECT  0 26.16 0.084 26.184 ;
    END
  END i[32]
  PIN i[33]
    DIRECTION INPUT ;
    USE SIGNAL ;
    PORT
      LAYER M4 ;
        RECT  0 26.256 0.084 26.28 ;
    END
  END i[33]
  PIN i[34]
    DIRECTION INPUT ;
    USE SIGNAL ;
    PORT
      LAYER M4 ;
        RECT  0 26.352 0.084 26.376 ;
    END
  END i[34]
  PIN i[35]
    DIRECTION INPUT ;
    USE SIGNAL ;
    PORT
      LAYER M4 ;
        RECT  0 26.448 0.084 26.472 ;
    END
  END i[35]
  PIN i[36]
    DIRECTION INPUT ;
    USE SIGNAL ;
    PORT
      LAYER M4 ;
        RECT  0 26.544 0.084 26.568 ;
    END
  END i[36]
  PIN i[37]
    DIRECTION INPUT ;
    USE SIGNAL ;
    PORT
      LAYER M4 ;
        RECT  0 26.64 0.084 26.664 ;
    END
  END i[37]
  PIN i[38]
    DIRECTION INPUT ;
    USE SIGNAL ;
    PORT
      LAYER M4 ;
        RECT  0 26.736 0.084 26.76 ;
    END
  END i[38]
  PIN i[39]
    DIRECTION INPUT ;
    USE SIGNAL ;
    PORT
      LAYER M4 ;
        RECT  0 26.832 0.084 26.856 ;
    END
  END i[39]
  PIN i[3]
    DIRECTION INPUT ;
    USE SIGNAL ;
    PORT
      LAYER M4 ;
        RECT  0 20.304 0.084 20.328 ;
    END
  END i[3]
  PIN i[40]
    DIRECTION INPUT ;
    USE SIGNAL ;
    PORT
      LAYER M4 ;
        RECT  0 26.928 0.084 26.952 ;
    END
  END i[40]
  PIN i[41]
    DIRECTION INPUT ;
    USE SIGNAL ;
    PORT
      LAYER M4 ;
        RECT  0 27.024 0.084 27.048 ;
    END
  END i[41]
  PIN i[42]
    DIRECTION INPUT ;
    USE SIGNAL ;
    PORT
      LAYER M4 ;
        RECT  0 27.12 0.084 27.144 ;
    END
  END i[42]
  PIN i[43]
    DIRECTION INPUT ;
    USE SIGNAL ;
    PORT
      LAYER M4 ;
        RECT  0 27.216 0.084 27.24 ;
    END
  END i[43]
  PIN i[44]
    DIRECTION INPUT ;
    USE SIGNAL ;
    PORT
      LAYER M4 ;
        RECT  0 27.312 0.084 27.336 ;
    END
  END i[44]
  PIN i[45]
    DIRECTION INPUT ;
    USE SIGNAL ;
    PORT
      LAYER M4 ;
        RECT  0 27.408 0.084 27.432 ;
    END
  END i[45]
  PIN i[46]
    DIRECTION INPUT ;
    USE SIGNAL ;
    PORT
      LAYER M4 ;
        RECT  0 27.504 0.084 27.528 ;
    END
  END i[46]
  PIN i[47]
    DIRECTION INPUT ;
    USE SIGNAL ;
    PORT
      LAYER M4 ;
        RECT  0 27.6 0.084 27.624 ;
    END
  END i[47]
  PIN i[48]
    DIRECTION INPUT ;
    USE SIGNAL ;
    PORT
      LAYER M4 ;
        RECT  0 27.696 0.084 27.72 ;
    END
  END i[48]
  PIN i[49]
    DIRECTION INPUT ;
    USE SIGNAL ;
    PORT
      LAYER M4 ;
        RECT  0 27.792 0.084 27.816 ;
    END
  END i[49]
  PIN i[4]
    DIRECTION INPUT ;
    USE SIGNAL ;
    PORT
      LAYER M4 ;
        RECT  0 20.4 0.084 20.424 ;
    END
  END i[4]
  PIN i[50]
    DIRECTION INPUT ;
    USE SIGNAL ;
    PORT
      LAYER M4 ;
        RECT  0 27.888 0.084 27.912 ;
    END
  END i[50]
  PIN i[51]
    DIRECTION INPUT ;
    USE SIGNAL ;
    PORT
      LAYER M4 ;
        RECT  0 27.984 0.084 28.008 ;
    END
  END i[51]
  PIN i[52]
    DIRECTION INPUT ;
    USE SIGNAL ;
    PORT
      LAYER M4 ;
        RECT  0 28.08 0.084 28.104 ;
    END
  END i[52]
  PIN i[53]
    DIRECTION INPUT ;
    USE SIGNAL ;
    PORT
      LAYER M4 ;
        RECT  0 28.176 0.084 28.2 ;
    END
  END i[53]
  PIN i[54]
    DIRECTION INPUT ;
    USE SIGNAL ;
    PORT
      LAYER M4 ;
        RECT  0 28.272 0.084 28.296 ;
    END
  END i[54]
  PIN i[55]
    DIRECTION INPUT ;
    USE SIGNAL ;
    PORT
      LAYER M4 ;
        RECT  0 28.368 0.084 28.392 ;
    END
  END i[55]
  PIN i[56]
    DIRECTION INPUT ;
    USE SIGNAL ;
    PORT
      LAYER M4 ;
        RECT  0 28.464 0.084 28.488 ;
    END
  END i[56]
  PIN i[57]
    DIRECTION INPUT ;
    USE SIGNAL ;
    PORT
      LAYER M4 ;
        RECT  0 28.56 0.084 28.584 ;
    END
  END i[57]
  PIN i[58]
    DIRECTION INPUT ;
    USE SIGNAL ;
    PORT
      LAYER M4 ;
        RECT  0 28.656 0.084 28.68 ;
    END
  END i[58]
  PIN i[59]
    DIRECTION INPUT ;
    USE SIGNAL ;
    PORT
      LAYER M4 ;
        RECT  0 28.752 0.084 28.776 ;
    END
  END i[59]
  PIN i[5]
    DIRECTION INPUT ;
    USE SIGNAL ;
    PORT
      LAYER M4 ;
        RECT  0 20.496 0.084 20.52 ;
    END
  END i[5]
  PIN i[60]
    DIRECTION INPUT ;
    USE SIGNAL ;
    PORT
      LAYER M4 ;
        RECT  0 28.848 0.084 28.872 ;
    END
  END i[60]
  PIN i[61]
    DIRECTION INPUT ;
    USE SIGNAL ;
    PORT
      LAYER M4 ;
        RECT  0 28.944 0.084 28.968 ;
    END
  END i[61]
  PIN i[62]
    DIRECTION INPUT ;
    USE SIGNAL ;
    PORT
      LAYER M4 ;
        RECT  0 29.04 0.084 29.064 ;
    END
  END i[62]
  PIN i[63]
    DIRECTION INPUT ;
    USE SIGNAL ;
    PORT
      LAYER M4 ;
        RECT  0 29.136 0.084 29.16 ;
    END
  END i[63]
  PIN i[64]
    DIRECTION INPUT ;
    USE SIGNAL ;
    PORT
      LAYER M4 ;
        RECT  0 13.872 0.084 13.896 ;
    END
  END i[64]
  PIN i[65]
    DIRECTION INPUT ;
    USE SIGNAL ;
    PORT
      LAYER M4 ;
        RECT  0 13.968 0.084 13.992 ;
    END
  END i[65]
  PIN i[66]
    DIRECTION INPUT ;
    USE SIGNAL ;
    PORT
      LAYER M4 ;
        RECT  0 14.064 0.084 14.088 ;
    END
  END i[66]
  PIN i[67]
    DIRECTION INPUT ;
    USE SIGNAL ;
    PORT
      LAYER M4 ;
        RECT  0 14.16 0.084 14.184 ;
    END
  END i[67]
  PIN i[68]
    DIRECTION INPUT ;
    USE SIGNAL ;
    PORT
      LAYER M4 ;
        RECT  0 14.256 0.084 14.28 ;
    END
  END i[68]
  PIN i[69]
    DIRECTION INPUT ;
    USE SIGNAL ;
    PORT
      LAYER M4 ;
        RECT  0 14.352 0.084 14.376 ;
    END
  END i[69]
  PIN i[6]
    DIRECTION INPUT ;
    USE SIGNAL ;
    PORT
      LAYER M4 ;
        RECT  0 20.592 0.084 20.616 ;
    END
  END i[6]
  PIN i[70]
    DIRECTION INPUT ;
    USE SIGNAL ;
    PORT
      LAYER M4 ;
        RECT  0 14.448 0.084 14.472 ;
    END
  END i[70]
  PIN i[71]
    DIRECTION INPUT ;
    USE SIGNAL ;
    PORT
      LAYER M4 ;
        RECT  0 14.544 0.084 14.568 ;
    END
  END i[71]
  PIN i[72]
    DIRECTION INPUT ;
    USE SIGNAL ;
    PORT
      LAYER M4 ;
        RECT  0 14.64 0.084 14.664 ;
    END
  END i[72]
  PIN i[73]
    DIRECTION INPUT ;
    USE SIGNAL ;
    PORT
      LAYER M4 ;
        RECT  0 14.736 0.084 14.76 ;
    END
  END i[73]
  PIN i[74]
    DIRECTION INPUT ;
    USE SIGNAL ;
    PORT
      LAYER M4 ;
        RECT  0 14.832 0.084 14.856 ;
    END
  END i[74]
  PIN i[75]
    DIRECTION INPUT ;
    USE SIGNAL ;
    PORT
      LAYER M4 ;
        RECT  0 14.928 0.084 14.952 ;
    END
  END i[75]
  PIN i[76]
    DIRECTION INPUT ;
    USE SIGNAL ;
    PORT
      LAYER M4 ;
        RECT  0 15.024 0.084 15.048 ;
    END
  END i[76]
  PIN i[77]
    DIRECTION INPUT ;
    USE SIGNAL ;
    PORT
      LAYER M4 ;
        RECT  0 15.12 0.084 15.144 ;
    END
  END i[77]
  PIN i[78]
    DIRECTION INPUT ;
    USE SIGNAL ;
    PORT
      LAYER M4 ;
        RECT  0 15.216 0.084 15.24 ;
    END
  END i[78]
  PIN i[79]
    DIRECTION INPUT ;
    USE SIGNAL ;
    PORT
      LAYER M4 ;
        RECT  0 15.312 0.084 15.336 ;
    END
  END i[79]
  PIN i[7]
    DIRECTION INPUT ;
    USE SIGNAL ;
    PORT
      LAYER M4 ;
        RECT  0 20.688 0.084 20.712 ;
    END
  END i[7]
  PIN i[80]
    DIRECTION INPUT ;
    USE SIGNAL ;
    PORT
      LAYER M4 ;
        RECT  0 15.408 0.084 15.432 ;
    END
  END i[80]
  PIN i[81]
    DIRECTION INPUT ;
    USE SIGNAL ;
    PORT
      LAYER M4 ;
        RECT  0 15.504 0.084 15.528 ;
    END
  END i[81]
  PIN i[82]
    DIRECTION INPUT ;
    USE SIGNAL ;
    PORT
      LAYER M4 ;
        RECT  0 15.6 0.084 15.624 ;
    END
  END i[82]
  PIN i[83]
    DIRECTION INPUT ;
    USE SIGNAL ;
    PORT
      LAYER M4 ;
        RECT  0 15.696 0.084 15.72 ;
    END
  END i[83]
  PIN i[84]
    DIRECTION INPUT ;
    USE SIGNAL ;
    PORT
      LAYER M4 ;
        RECT  0 15.792 0.084 15.816 ;
    END
  END i[84]
  PIN i[85]
    DIRECTION INPUT ;
    USE SIGNAL ;
    PORT
      LAYER M4 ;
        RECT  0 15.888 0.084 15.912 ;
    END
  END i[85]
  PIN i[86]
    DIRECTION INPUT ;
    USE SIGNAL ;
    PORT
      LAYER M4 ;
        RECT  0 15.984 0.084 16.008 ;
    END
  END i[86]
  PIN i[87]
    DIRECTION INPUT ;
    USE SIGNAL ;
    PORT
      LAYER M4 ;
        RECT  0 16.08 0.084 16.104 ;
    END
  END i[87]
  PIN i[88]
    DIRECTION INPUT ;
    USE SIGNAL ;
    PORT
      LAYER M4 ;
        RECT  0 16.176 0.084 16.2 ;
    END
  END i[88]
  PIN i[89]
    DIRECTION INPUT ;
    USE SIGNAL ;
    PORT
      LAYER M4 ;
        RECT  0 16.272 0.084 16.296 ;
    END
  END i[89]
  PIN i[8]
    DIRECTION INPUT ;
    USE SIGNAL ;
    PORT
      LAYER M4 ;
        RECT  0 20.784 0.084 20.808 ;
    END
  END i[8]
  PIN i[90]
    DIRECTION INPUT ;
    USE SIGNAL ;
    PORT
      LAYER M4 ;
        RECT  0 16.368 0.084 16.392 ;
    END
  END i[90]
  PIN i[91]
    DIRECTION INPUT ;
    USE SIGNAL ;
    PORT
      LAYER M4 ;
        RECT  0 16.464 0.084 16.488 ;
    END
  END i[91]
  PIN i[92]
    DIRECTION INPUT ;
    USE SIGNAL ;
    PORT
      LAYER M4 ;
        RECT  0 16.56 0.084 16.584 ;
    END
  END i[92]
  PIN i[93]
    DIRECTION INPUT ;
    USE SIGNAL ;
    PORT
      LAYER M4 ;
        RECT  0 16.656 0.084 16.68 ;
    END
  END i[93]
  PIN i[94]
    DIRECTION INPUT ;
    USE SIGNAL ;
    PORT
      LAYER M4 ;
        RECT  0 16.752 0.084 16.776 ;
    END
  END i[94]
  PIN i[95]
    DIRECTION INPUT ;
    USE SIGNAL ;
    PORT
      LAYER M4 ;
        RECT  0 16.848 0.084 16.872 ;
    END
  END i[95]
  PIN i[96]
    DIRECTION INPUT ;
    USE SIGNAL ;
    PORT
      LAYER M4 ;
        RECT  0 10.8 0.084 10.824 ;
    END
  END i[96]
  PIN i[97]
    DIRECTION INPUT ;
    USE SIGNAL ;
    PORT
      LAYER M4 ;
        RECT  0 10.896 0.084 10.92 ;
    END
  END i[97]
  PIN i[98]
    DIRECTION INPUT ;
    USE SIGNAL ;
    PORT
      LAYER M4 ;
        RECT  0 10.992 0.084 11.016 ;
    END
  END i[98]
  PIN i[99]
    DIRECTION INPUT ;
    USE SIGNAL ;
    PORT
      LAYER M4 ;
        RECT  0 11.088 0.084 11.112 ;
    END
  END i[99]
  PIN i[9]
    DIRECTION INPUT ;
    USE SIGNAL ;
    PORT
      LAYER M4 ;
        RECT  0 20.88 0.084 20.904 ;
    END
  END i[9]
  PIN o[0]
    DIRECTION OUTPUT ;
    USE SIGNAL ;
    PORT
      LAYER M4 ;
        RECT  0 34.128 0.084 34.152 ;
    END
  END o[0]
  PIN o[100]
    DIRECTION OUTPUT ;
    USE SIGNAL ;
    PORT
      LAYER M4 ;
        RECT  0 41.424 0.084 41.448 ;
    END
  END o[100]
  PIN o[101]
    DIRECTION OUTPUT ;
    USE SIGNAL ;
    PORT
      LAYER M4 ;
        RECT  0 41.52 0.084 41.544 ;
    END
  END o[101]
  PIN o[102]
    DIRECTION OUTPUT ;
    USE SIGNAL ;
    PORT
      LAYER M4 ;
        RECT  0 41.616 0.084 41.64 ;
    END
  END o[102]
  PIN o[103]
    DIRECTION OUTPUT ;
    USE SIGNAL ;
    PORT
      LAYER M4 ;
        RECT  0 41.712 0.084 41.736 ;
    END
  END o[103]
  PIN o[104]
    DIRECTION OUTPUT ;
    USE SIGNAL ;
    PORT
      LAYER M4 ;
        RECT  0 41.808 0.084 41.832 ;
    END
  END o[104]
  PIN o[105]
    DIRECTION OUTPUT ;
    USE SIGNAL ;
    PORT
      LAYER M4 ;
        RECT  0 41.904 0.084 41.928 ;
    END
  END o[105]
  PIN o[106]
    DIRECTION OUTPUT ;
    USE SIGNAL ;
    PORT
      LAYER M4 ;
        RECT  0 42 0.084 42.024 ;
    END
  END o[106]
  PIN o[107]
    DIRECTION OUTPUT ;
    USE SIGNAL ;
    PORT
      LAYER M4 ;
        RECT  0 42.096 0.084 42.12 ;
    END
  END o[107]
  PIN o[108]
    DIRECTION OUTPUT ;
    USE SIGNAL ;
    PORT
      LAYER M4 ;
        RECT  0 42.192 0.084 42.216 ;
    END
  END o[108]
  PIN o[109]
    DIRECTION OUTPUT ;
    USE SIGNAL ;
    PORT
      LAYER M4 ;
        RECT  0 42.288 0.084 42.312 ;
    END
  END o[109]
  PIN o[10]
    DIRECTION OUTPUT ;
    USE SIGNAL ;
    PORT
      LAYER M4 ;
        RECT  0 35.088 0.084 35.112 ;
    END
  END o[10]
  PIN o[110]
    DIRECTION OUTPUT ;
    USE SIGNAL ;
    PORT
      LAYER M4 ;
        RECT  0 42.384 0.084 42.408 ;
    END
  END o[110]
  PIN o[111]
    DIRECTION OUTPUT ;
    USE SIGNAL ;
    PORT
      LAYER M4 ;
        RECT  0 42.48 0.084 42.504 ;
    END
  END o[111]
  PIN o[112]
    DIRECTION OUTPUT ;
    USE SIGNAL ;
    PORT
      LAYER M4 ;
        RECT  0 42.576 0.084 42.6 ;
    END
  END o[112]
  PIN o[113]
    DIRECTION OUTPUT ;
    USE SIGNAL ;
    PORT
      LAYER M4 ;
        RECT  0 42.672 0.084 42.696 ;
    END
  END o[113]
  PIN o[114]
    DIRECTION OUTPUT ;
    USE SIGNAL ;
    PORT
      LAYER M4 ;
        RECT  0 42.768 0.084 42.792 ;
    END
  END o[114]
  PIN o[115]
    DIRECTION OUTPUT ;
    USE SIGNAL ;
    PORT
      LAYER M4 ;
        RECT  0 42.864 0.084 42.888 ;
    END
  END o[115]
  PIN o[116]
    DIRECTION OUTPUT ;
    USE SIGNAL ;
    PORT
      LAYER M4 ;
        RECT  0 42.96 0.084 42.984 ;
    END
  END o[116]
  PIN o[117]
    DIRECTION OUTPUT ;
    USE SIGNAL ;
    PORT
      LAYER M4 ;
        RECT  0 43.056 0.084 43.08 ;
    END
  END o[117]
  PIN o[118]
    DIRECTION OUTPUT ;
    USE SIGNAL ;
    PORT
      LAYER M4 ;
        RECT  0 43.152 0.084 43.176 ;
    END
  END o[118]
  PIN o[119]
    DIRECTION OUTPUT ;
    USE SIGNAL ;
    PORT
      LAYER M4 ;
        RECT  0 43.248 0.084 43.272 ;
    END
  END o[119]
  PIN o[11]
    DIRECTION OUTPUT ;
    USE SIGNAL ;
    PORT
      LAYER M4 ;
        RECT  0 35.184 0.084 35.208 ;
    END
  END o[11]
  PIN o[120]
    DIRECTION OUTPUT ;
    USE SIGNAL ;
    PORT
      LAYER M4 ;
        RECT  0 43.344 0.084 43.368 ;
    END
  END o[120]
  PIN o[121]
    DIRECTION OUTPUT ;
    USE SIGNAL ;
    PORT
      LAYER M4 ;
        RECT  0 43.44 0.084 43.464 ;
    END
  END o[121]
  PIN o[122]
    DIRECTION OUTPUT ;
    USE SIGNAL ;
    PORT
      LAYER M4 ;
        RECT  0 43.536 0.084 43.56 ;
    END
  END o[122]
  PIN o[123]
    DIRECTION OUTPUT ;
    USE SIGNAL ;
    PORT
      LAYER M4 ;
        RECT  0 43.632 0.084 43.656 ;
    END
  END o[123]
  PIN o[124]
    DIRECTION OUTPUT ;
    USE SIGNAL ;
    PORT
      LAYER M4 ;
        RECT  0 43.728 0.084 43.752 ;
    END
  END o[124]
  PIN o[125]
    DIRECTION OUTPUT ;
    USE SIGNAL ;
    PORT
      LAYER M4 ;
        RECT  0 43.824 0.084 43.848 ;
    END
  END o[125]
  PIN o[126]
    DIRECTION OUTPUT ;
    USE SIGNAL ;
    PORT
      LAYER M4 ;
        RECT  0 43.92 0.084 43.944 ;
    END
  END o[126]
  PIN o[127]
    DIRECTION OUTPUT ;
    USE SIGNAL ;
    PORT
      LAYER M4 ;
        RECT  0 44.016 0.084 44.04 ;
    END
  END o[127]
  PIN o[128]
    DIRECTION OUTPUT ;
    USE SIGNAL ;
    PORT
      LAYER M4 ;
        RECT  0 50.256 0.084 50.28 ;
    END
  END o[128]
  PIN o[129]
    DIRECTION OUTPUT ;
    USE SIGNAL ;
    PORT
      LAYER M4 ;
        RECT  0 50.352 0.084 50.376 ;
    END
  END o[129]
  PIN o[12]
    DIRECTION OUTPUT ;
    USE SIGNAL ;
    PORT
      LAYER M4 ;
        RECT  0 35.28 0.084 35.304 ;
    END
  END o[12]
  PIN o[130]
    DIRECTION OUTPUT ;
    USE SIGNAL ;
    PORT
      LAYER M4 ;
        RECT  0 50.448 0.084 50.472 ;
    END
  END o[130]
  PIN o[131]
    DIRECTION OUTPUT ;
    USE SIGNAL ;
    PORT
      LAYER M4 ;
        RECT  0 50.544 0.084 50.568 ;
    END
  END o[131]
  PIN o[132]
    DIRECTION OUTPUT ;
    USE SIGNAL ;
    PORT
      LAYER M4 ;
        RECT  0 50.64 0.084 50.664 ;
    END
  END o[132]
  PIN o[133]
    DIRECTION OUTPUT ;
    USE SIGNAL ;
    PORT
      LAYER M4 ;
        RECT  0 50.736 0.084 50.76 ;
    END
  END o[133]
  PIN o[134]
    DIRECTION OUTPUT ;
    USE SIGNAL ;
    PORT
      LAYER M4 ;
        RECT  0 50.832 0.084 50.856 ;
    END
  END o[134]
  PIN o[135]
    DIRECTION OUTPUT ;
    USE SIGNAL ;
    PORT
      LAYER M4 ;
        RECT  0 50.928 0.084 50.952 ;
    END
  END o[135]
  PIN o[136]
    DIRECTION OUTPUT ;
    USE SIGNAL ;
    PORT
      LAYER M4 ;
        RECT  0 51.024 0.084 51.048 ;
    END
  END o[136]
  PIN o[137]
    DIRECTION OUTPUT ;
    USE SIGNAL ;
    PORT
      LAYER M4 ;
        RECT  0 51.12 0.084 51.144 ;
    END
  END o[137]
  PIN o[138]
    DIRECTION OUTPUT ;
    USE SIGNAL ;
    PORT
      LAYER M4 ;
        RECT  0 51.216 0.084 51.24 ;
    END
  END o[138]
  PIN o[139]
    DIRECTION OUTPUT ;
    USE SIGNAL ;
    PORT
      LAYER M4 ;
        RECT  0 51.312 0.084 51.336 ;
    END
  END o[139]
  PIN o[13]
    DIRECTION OUTPUT ;
    USE SIGNAL ;
    PORT
      LAYER M4 ;
        RECT  0 35.376 0.084 35.4 ;
    END
  END o[13]
  PIN o[140]
    DIRECTION OUTPUT ;
    USE SIGNAL ;
    PORT
      LAYER M4 ;
        RECT  0 51.408 0.084 51.432 ;
    END
  END o[140]
  PIN o[141]
    DIRECTION OUTPUT ;
    USE SIGNAL ;
    PORT
      LAYER M4 ;
        RECT  0 51.504 0.084 51.528 ;
    END
  END o[141]
  PIN o[142]
    DIRECTION OUTPUT ;
    USE SIGNAL ;
    PORT
      LAYER M4 ;
        RECT  0 51.6 0.084 51.624 ;
    END
  END o[142]
  PIN o[143]
    DIRECTION OUTPUT ;
    USE SIGNAL ;
    PORT
      LAYER M4 ;
        RECT  0 51.696 0.084 51.72 ;
    END
  END o[143]
  PIN o[144]
    DIRECTION OUTPUT ;
    USE SIGNAL ;
    PORT
      LAYER M4 ;
        RECT  0 51.792 0.084 51.816 ;
    END
  END o[144]
  PIN o[145]
    DIRECTION OUTPUT ;
    USE SIGNAL ;
    PORT
      LAYER M4 ;
        RECT  0 51.888 0.084 51.912 ;
    END
  END o[145]
  PIN o[146]
    DIRECTION OUTPUT ;
    USE SIGNAL ;
    PORT
      LAYER M4 ;
        RECT  0 51.984 0.084 52.008 ;
    END
  END o[146]
  PIN o[147]
    DIRECTION OUTPUT ;
    USE SIGNAL ;
    PORT
      LAYER M4 ;
        RECT  0 52.08 0.084 52.104 ;
    END
  END o[147]
  PIN o[148]
    DIRECTION OUTPUT ;
    USE SIGNAL ;
    PORT
      LAYER M4 ;
        RECT  0 52.176 0.084 52.2 ;
    END
  END o[148]
  PIN o[149]
    DIRECTION OUTPUT ;
    USE SIGNAL ;
    PORT
      LAYER M4 ;
        RECT  0 52.272 0.084 52.296 ;
    END
  END o[149]
  PIN o[14]
    DIRECTION OUTPUT ;
    USE SIGNAL ;
    PORT
      LAYER M4 ;
        RECT  0 35.472 0.084 35.496 ;
    END
  END o[14]
  PIN o[150]
    DIRECTION OUTPUT ;
    USE SIGNAL ;
    PORT
      LAYER M4 ;
        RECT  0 52.368 0.084 52.392 ;
    END
  END o[150]
  PIN o[151]
    DIRECTION OUTPUT ;
    USE SIGNAL ;
    PORT
      LAYER M4 ;
        RECT  0 52.464 0.084 52.488 ;
    END
  END o[151]
  PIN o[152]
    DIRECTION OUTPUT ;
    USE SIGNAL ;
    PORT
      LAYER M4 ;
        RECT  0 52.56 0.084 52.584 ;
    END
  END o[152]
  PIN o[153]
    DIRECTION OUTPUT ;
    USE SIGNAL ;
    PORT
      LAYER M4 ;
        RECT  0 52.656 0.084 52.68 ;
    END
  END o[153]
  PIN o[154]
    DIRECTION OUTPUT ;
    USE SIGNAL ;
    PORT
      LAYER M4 ;
        RECT  0 52.752 0.084 52.776 ;
    END
  END o[154]
  PIN o[155]
    DIRECTION OUTPUT ;
    USE SIGNAL ;
    PORT
      LAYER M4 ;
        RECT  0 52.848 0.084 52.872 ;
    END
  END o[155]
  PIN o[156]
    DIRECTION OUTPUT ;
    USE SIGNAL ;
    PORT
      LAYER M4 ;
        RECT  0 52.944 0.084 52.968 ;
    END
  END o[156]
  PIN o[157]
    DIRECTION OUTPUT ;
    USE SIGNAL ;
    PORT
      LAYER M4 ;
        RECT  0 53.04 0.084 53.064 ;
    END
  END o[157]
  PIN o[158]
    DIRECTION OUTPUT ;
    USE SIGNAL ;
    PORT
      LAYER M4 ;
        RECT  0 53.136 0.084 53.16 ;
    END
  END o[158]
  PIN o[159]
    DIRECTION OUTPUT ;
    USE SIGNAL ;
    PORT
      LAYER M4 ;
        RECT  0 53.232 0.084 53.256 ;
    END
  END o[159]
  PIN o[15]
    DIRECTION OUTPUT ;
    USE SIGNAL ;
    PORT
      LAYER M4 ;
        RECT  0 35.568 0.084 35.592 ;
    END
  END o[15]
  PIN o[160]
    DIRECTION OUTPUT ;
    USE SIGNAL ;
    PORT
      LAYER M4 ;
        RECT  0 44.112 0.084 44.136 ;
    END
  END o[160]
  PIN o[161]
    DIRECTION OUTPUT ;
    USE SIGNAL ;
    PORT
      LAYER M4 ;
        RECT  0 44.208 0.084 44.232 ;
    END
  END o[161]
  PIN o[162]
    DIRECTION OUTPUT ;
    USE SIGNAL ;
    PORT
      LAYER M4 ;
        RECT  0 44.304 0.084 44.328 ;
    END
  END o[162]
  PIN o[163]
    DIRECTION OUTPUT ;
    USE SIGNAL ;
    PORT
      LAYER M4 ;
        RECT  0 44.4 0.084 44.424 ;
    END
  END o[163]
  PIN o[164]
    DIRECTION OUTPUT ;
    USE SIGNAL ;
    PORT
      LAYER M4 ;
        RECT  0 44.496 0.084 44.52 ;
    END
  END o[164]
  PIN o[165]
    DIRECTION OUTPUT ;
    USE SIGNAL ;
    PORT
      LAYER M4 ;
        RECT  0 44.592 0.084 44.616 ;
    END
  END o[165]
  PIN o[166]
    DIRECTION OUTPUT ;
    USE SIGNAL ;
    PORT
      LAYER M4 ;
        RECT  0 44.688 0.084 44.712 ;
    END
  END o[166]
  PIN o[167]
    DIRECTION OUTPUT ;
    USE SIGNAL ;
    PORT
      LAYER M4 ;
        RECT  0 44.784 0.084 44.808 ;
    END
  END o[167]
  PIN o[168]
    DIRECTION OUTPUT ;
    USE SIGNAL ;
    PORT
      LAYER M4 ;
        RECT  0 44.88 0.084 44.904 ;
    END
  END o[168]
  PIN o[169]
    DIRECTION OUTPUT ;
    USE SIGNAL ;
    PORT
      LAYER M4 ;
        RECT  0 44.976 0.084 45 ;
    END
  END o[169]
  PIN o[16]
    DIRECTION OUTPUT ;
    USE SIGNAL ;
    PORT
      LAYER M4 ;
        RECT  0 35.664 0.084 35.688 ;
    END
  END o[16]
  PIN o[170]
    DIRECTION OUTPUT ;
    USE SIGNAL ;
    PORT
      LAYER M4 ;
        RECT  0 45.072 0.084 45.096 ;
    END
  END o[170]
  PIN o[171]
    DIRECTION OUTPUT ;
    USE SIGNAL ;
    PORT
      LAYER M4 ;
        RECT  0 45.168 0.084 45.192 ;
    END
  END o[171]
  PIN o[172]
    DIRECTION OUTPUT ;
    USE SIGNAL ;
    PORT
      LAYER M4 ;
        RECT  0 45.264 0.084 45.288 ;
    END
  END o[172]
  PIN o[173]
    DIRECTION OUTPUT ;
    USE SIGNAL ;
    PORT
      LAYER M4 ;
        RECT  0 45.36 0.084 45.384 ;
    END
  END o[173]
  PIN o[174]
    DIRECTION OUTPUT ;
    USE SIGNAL ;
    PORT
      LAYER M4 ;
        RECT  0 45.456 0.084 45.48 ;
    END
  END o[174]
  PIN o[175]
    DIRECTION OUTPUT ;
    USE SIGNAL ;
    PORT
      LAYER M4 ;
        RECT  0 45.552 0.084 45.576 ;
    END
  END o[175]
  PIN o[176]
    DIRECTION OUTPUT ;
    USE SIGNAL ;
    PORT
      LAYER M4 ;
        RECT  0 45.648 0.084 45.672 ;
    END
  END o[176]
  PIN o[177]
    DIRECTION OUTPUT ;
    USE SIGNAL ;
    PORT
      LAYER M4 ;
        RECT  0 45.744 0.084 45.768 ;
    END
  END o[177]
  PIN o[178]
    DIRECTION OUTPUT ;
    USE SIGNAL ;
    PORT
      LAYER M4 ;
        RECT  0 45.84 0.084 45.864 ;
    END
  END o[178]
  PIN o[179]
    DIRECTION OUTPUT ;
    USE SIGNAL ;
    PORT
      LAYER M4 ;
        RECT  0 45.936 0.084 45.96 ;
    END
  END o[179]
  PIN o[17]
    DIRECTION OUTPUT ;
    USE SIGNAL ;
    PORT
      LAYER M4 ;
        RECT  0 35.76 0.084 35.784 ;
    END
  END o[17]
  PIN o[180]
    DIRECTION OUTPUT ;
    USE SIGNAL ;
    PORT
      LAYER M4 ;
        RECT  0 46.032 0.084 46.056 ;
    END
  END o[180]
  PIN o[181]
    DIRECTION OUTPUT ;
    USE SIGNAL ;
    PORT
      LAYER M4 ;
        RECT  0 46.128 0.084 46.152 ;
    END
  END o[181]
  PIN o[182]
    DIRECTION OUTPUT ;
    USE SIGNAL ;
    PORT
      LAYER M4 ;
        RECT  0 46.224 0.084 46.248 ;
    END
  END o[182]
  PIN o[183]
    DIRECTION OUTPUT ;
    USE SIGNAL ;
    PORT
      LAYER M4 ;
        RECT  0 46.32 0.084 46.344 ;
    END
  END o[183]
  PIN o[184]
    DIRECTION OUTPUT ;
    USE SIGNAL ;
    PORT
      LAYER M4 ;
        RECT  0 46.416 0.084 46.44 ;
    END
  END o[184]
  PIN o[185]
    DIRECTION OUTPUT ;
    USE SIGNAL ;
    PORT
      LAYER M4 ;
        RECT  0 46.512 0.084 46.536 ;
    END
  END o[185]
  PIN o[186]
    DIRECTION OUTPUT ;
    USE SIGNAL ;
    PORT
      LAYER M4 ;
        RECT  0 46.608 0.084 46.632 ;
    END
  END o[186]
  PIN o[187]
    DIRECTION OUTPUT ;
    USE SIGNAL ;
    PORT
      LAYER M4 ;
        RECT  0 46.704 0.084 46.728 ;
    END
  END o[187]
  PIN o[188]
    DIRECTION OUTPUT ;
    USE SIGNAL ;
    PORT
      LAYER M4 ;
        RECT  0 46.8 0.084 46.824 ;
    END
  END o[188]
  PIN o[189]
    DIRECTION OUTPUT ;
    USE SIGNAL ;
    PORT
      LAYER M4 ;
        RECT  0 46.896 0.084 46.92 ;
    END
  END o[189]
  PIN o[18]
    DIRECTION OUTPUT ;
    USE SIGNAL ;
    PORT
      LAYER M4 ;
        RECT  0 35.856 0.084 35.88 ;
    END
  END o[18]
  PIN o[190]
    DIRECTION OUTPUT ;
    USE SIGNAL ;
    PORT
      LAYER M4 ;
        RECT  0 46.992 0.084 47.016 ;
    END
  END o[190]
  PIN o[191]
    DIRECTION OUTPUT ;
    USE SIGNAL ;
    PORT
      LAYER M4 ;
        RECT  0 47.088 0.084 47.112 ;
    END
  END o[191]
  PIN o[192]
    DIRECTION OUTPUT ;
    USE SIGNAL ;
    PORT
      LAYER M4 ;
        RECT  0 56.4 0.084 56.424 ;
    END
  END o[192]
  PIN o[193]
    DIRECTION OUTPUT ;
    USE SIGNAL ;
    PORT
      LAYER M4 ;
        RECT  0 56.496 0.084 56.52 ;
    END
  END o[193]
  PIN o[194]
    DIRECTION OUTPUT ;
    USE SIGNAL ;
    PORT
      LAYER M4 ;
        RECT  0 56.592 0.084 56.616 ;
    END
  END o[194]
  PIN o[195]
    DIRECTION OUTPUT ;
    USE SIGNAL ;
    PORT
      LAYER M4 ;
        RECT  0 56.688 0.084 56.712 ;
    END
  END o[195]
  PIN o[196]
    DIRECTION OUTPUT ;
    USE SIGNAL ;
    PORT
      LAYER M4 ;
        RECT  0 56.784 0.084 56.808 ;
    END
  END o[196]
  PIN o[197]
    DIRECTION OUTPUT ;
    USE SIGNAL ;
    PORT
      LAYER M4 ;
        RECT  0 56.88 0.084 56.904 ;
    END
  END o[197]
  PIN o[198]
    DIRECTION OUTPUT ;
    USE SIGNAL ;
    PORT
      LAYER M4 ;
        RECT  0 56.976 0.084 57 ;
    END
  END o[198]
  PIN o[199]
    DIRECTION OUTPUT ;
    USE SIGNAL ;
    PORT
      LAYER M4 ;
        RECT  0 57.072 0.084 57.096 ;
    END
  END o[199]
  PIN o[19]
    DIRECTION OUTPUT ;
    USE SIGNAL ;
    PORT
      LAYER M4 ;
        RECT  0 35.952 0.084 35.976 ;
    END
  END o[19]
  PIN o[1]
    DIRECTION OUTPUT ;
    USE SIGNAL ;
    PORT
      LAYER M4 ;
        RECT  0 34.224 0.084 34.248 ;
    END
  END o[1]
  PIN o[200]
    DIRECTION OUTPUT ;
    USE SIGNAL ;
    PORT
      LAYER M4 ;
        RECT  0 57.168 0.084 57.192 ;
    END
  END o[200]
  PIN o[201]
    DIRECTION OUTPUT ;
    USE SIGNAL ;
    PORT
      LAYER M4 ;
        RECT  0 57.264 0.084 57.288 ;
    END
  END o[201]
  PIN o[202]
    DIRECTION OUTPUT ;
    USE SIGNAL ;
    PORT
      LAYER M4 ;
        RECT  0 57.36 0.084 57.384 ;
    END
  END o[202]
  PIN o[203]
    DIRECTION OUTPUT ;
    USE SIGNAL ;
    PORT
      LAYER M4 ;
        RECT  0 57.456 0.084 57.48 ;
    END
  END o[203]
  PIN o[204]
    DIRECTION OUTPUT ;
    USE SIGNAL ;
    PORT
      LAYER M4 ;
        RECT  0 57.552 0.084 57.576 ;
    END
  END o[204]
  PIN o[205]
    DIRECTION OUTPUT ;
    USE SIGNAL ;
    PORT
      LAYER M4 ;
        RECT  0 57.648 0.084 57.672 ;
    END
  END o[205]
  PIN o[206]
    DIRECTION OUTPUT ;
    USE SIGNAL ;
    PORT
      LAYER M4 ;
        RECT  0 57.744 0.084 57.768 ;
    END
  END o[206]
  PIN o[207]
    DIRECTION OUTPUT ;
    USE SIGNAL ;
    PORT
      LAYER M4 ;
        RECT  0 57.84 0.084 57.864 ;
    END
  END o[207]
  PIN o[208]
    DIRECTION OUTPUT ;
    USE SIGNAL ;
    PORT
      LAYER M4 ;
        RECT  0 57.936 0.084 57.96 ;
    END
  END o[208]
  PIN o[209]
    DIRECTION OUTPUT ;
    USE SIGNAL ;
    PORT
      LAYER M4 ;
        RECT  0 58.032 0.084 58.056 ;
    END
  END o[209]
  PIN o[20]
    DIRECTION OUTPUT ;
    USE SIGNAL ;
    PORT
      LAYER M4 ;
        RECT  0 36.048 0.084 36.072 ;
    END
  END o[20]
  PIN o[210]
    DIRECTION OUTPUT ;
    USE SIGNAL ;
    PORT
      LAYER M4 ;
        RECT  0 58.128 0.084 58.152 ;
    END
  END o[210]
  PIN o[211]
    DIRECTION OUTPUT ;
    USE SIGNAL ;
    PORT
      LAYER M4 ;
        RECT  0 58.224 0.084 58.248 ;
    END
  END o[211]
  PIN o[212]
    DIRECTION OUTPUT ;
    USE SIGNAL ;
    PORT
      LAYER M4 ;
        RECT  0 58.32 0.084 58.344 ;
    END
  END o[212]
  PIN o[213]
    DIRECTION OUTPUT ;
    USE SIGNAL ;
    PORT
      LAYER M4 ;
        RECT  0 58.416 0.084 58.44 ;
    END
  END o[213]
  PIN o[214]
    DIRECTION OUTPUT ;
    USE SIGNAL ;
    PORT
      LAYER M4 ;
        RECT  0 58.512 0.084 58.536 ;
    END
  END o[214]
  PIN o[215]
    DIRECTION OUTPUT ;
    USE SIGNAL ;
    PORT
      LAYER M4 ;
        RECT  0 58.608 0.084 58.632 ;
    END
  END o[215]
  PIN o[216]
    DIRECTION OUTPUT ;
    USE SIGNAL ;
    PORT
      LAYER M4 ;
        RECT  0 58.704 0.084 58.728 ;
    END
  END o[216]
  PIN o[217]
    DIRECTION OUTPUT ;
    USE SIGNAL ;
    PORT
      LAYER M4 ;
        RECT  0 58.8 0.084 58.824 ;
    END
  END o[217]
  PIN o[218]
    DIRECTION OUTPUT ;
    USE SIGNAL ;
    PORT
      LAYER M4 ;
        RECT  0 58.896 0.084 58.92 ;
    END
  END o[218]
  PIN o[219]
    DIRECTION OUTPUT ;
    USE SIGNAL ;
    PORT
      LAYER M4 ;
        RECT  0 58.992 0.084 59.016 ;
    END
  END o[219]
  PIN o[21]
    DIRECTION OUTPUT ;
    USE SIGNAL ;
    PORT
      LAYER M4 ;
        RECT  0 36.144 0.084 36.168 ;
    END
  END o[21]
  PIN o[220]
    DIRECTION OUTPUT ;
    USE SIGNAL ;
    PORT
      LAYER M4 ;
        RECT  0 59.088 0.084 59.112 ;
    END
  END o[220]
  PIN o[221]
    DIRECTION OUTPUT ;
    USE SIGNAL ;
    PORT
      LAYER M4 ;
        RECT  0 59.184 0.084 59.208 ;
    END
  END o[221]
  PIN o[222]
    DIRECTION OUTPUT ;
    USE SIGNAL ;
    PORT
      LAYER M4 ;
        RECT  0 59.28 0.084 59.304 ;
    END
  END o[222]
  PIN o[223]
    DIRECTION OUTPUT ;
    USE SIGNAL ;
    PORT
      LAYER M4 ;
        RECT  0 59.376 0.084 59.4 ;
    END
  END o[223]
  PIN o[224]
    DIRECTION OUTPUT ;
    USE SIGNAL ;
    PORT
      LAYER M4 ;
        RECT  0 53.328 0.084 53.352 ;
    END
  END o[224]
  PIN o[225]
    DIRECTION OUTPUT ;
    USE SIGNAL ;
    PORT
      LAYER M4 ;
        RECT  0 53.424 0.084 53.448 ;
    END
  END o[225]
  PIN o[226]
    DIRECTION OUTPUT ;
    USE SIGNAL ;
    PORT
      LAYER M4 ;
        RECT  0 53.52 0.084 53.544 ;
    END
  END o[226]
  PIN o[227]
    DIRECTION OUTPUT ;
    USE SIGNAL ;
    PORT
      LAYER M4 ;
        RECT  0 53.616 0.084 53.64 ;
    END
  END o[227]
  PIN o[228]
    DIRECTION OUTPUT ;
    USE SIGNAL ;
    PORT
      LAYER M4 ;
        RECT  0 53.712 0.084 53.736 ;
    END
  END o[228]
  PIN o[229]
    DIRECTION OUTPUT ;
    USE SIGNAL ;
    PORT
      LAYER M4 ;
        RECT  0 53.808 0.084 53.832 ;
    END
  END o[229]
  PIN o[22]
    DIRECTION OUTPUT ;
    USE SIGNAL ;
    PORT
      LAYER M4 ;
        RECT  0 36.24 0.084 36.264 ;
    END
  END o[22]
  PIN o[230]
    DIRECTION OUTPUT ;
    USE SIGNAL ;
    PORT
      LAYER M4 ;
        RECT  0 53.904 0.084 53.928 ;
    END
  END o[230]
  PIN o[231]
    DIRECTION OUTPUT ;
    USE SIGNAL ;
    PORT
      LAYER M4 ;
        RECT  0 54 0.084 54.024 ;
    END
  END o[231]
  PIN o[232]
    DIRECTION OUTPUT ;
    USE SIGNAL ;
    PORT
      LAYER M4 ;
        RECT  0 54.096 0.084 54.12 ;
    END
  END o[232]
  PIN o[233]
    DIRECTION OUTPUT ;
    USE SIGNAL ;
    PORT
      LAYER M4 ;
        RECT  0 54.192 0.084 54.216 ;
    END
  END o[233]
  PIN o[234]
    DIRECTION OUTPUT ;
    USE SIGNAL ;
    PORT
      LAYER M4 ;
        RECT  0 54.288 0.084 54.312 ;
    END
  END o[234]
  PIN o[235]
    DIRECTION OUTPUT ;
    USE SIGNAL ;
    PORT
      LAYER M4 ;
        RECT  0 54.384 0.084 54.408 ;
    END
  END o[235]
  PIN o[236]
    DIRECTION OUTPUT ;
    USE SIGNAL ;
    PORT
      LAYER M4 ;
        RECT  0 54.48 0.084 54.504 ;
    END
  END o[236]
  PIN o[237]
    DIRECTION OUTPUT ;
    USE SIGNAL ;
    PORT
      LAYER M4 ;
        RECT  0 54.576 0.084 54.6 ;
    END
  END o[237]
  PIN o[238]
    DIRECTION OUTPUT ;
    USE SIGNAL ;
    PORT
      LAYER M4 ;
        RECT  0 54.672 0.084 54.696 ;
    END
  END o[238]
  PIN o[239]
    DIRECTION OUTPUT ;
    USE SIGNAL ;
    PORT
      LAYER M4 ;
        RECT  0 54.768 0.084 54.792 ;
    END
  END o[239]
  PIN o[23]
    DIRECTION OUTPUT ;
    USE SIGNAL ;
    PORT
      LAYER M4 ;
        RECT  0 36.336 0.084 36.36 ;
    END
  END o[23]
  PIN o[240]
    DIRECTION OUTPUT ;
    USE SIGNAL ;
    PORT
      LAYER M4 ;
        RECT  0 54.864 0.084 54.888 ;
    END
  END o[240]
  PIN o[241]
    DIRECTION OUTPUT ;
    USE SIGNAL ;
    PORT
      LAYER M4 ;
        RECT  0 54.96 0.084 54.984 ;
    END
  END o[241]
  PIN o[242]
    DIRECTION OUTPUT ;
    USE SIGNAL ;
    PORT
      LAYER M4 ;
        RECT  0 55.056 0.084 55.08 ;
    END
  END o[242]
  PIN o[243]
    DIRECTION OUTPUT ;
    USE SIGNAL ;
    PORT
      LAYER M4 ;
        RECT  0 55.152 0.084 55.176 ;
    END
  END o[243]
  PIN o[244]
    DIRECTION OUTPUT ;
    USE SIGNAL ;
    PORT
      LAYER M4 ;
        RECT  0 55.248 0.084 55.272 ;
    END
  END o[244]
  PIN o[245]
    DIRECTION OUTPUT ;
    USE SIGNAL ;
    PORT
      LAYER M4 ;
        RECT  0 55.344 0.084 55.368 ;
    END
  END o[245]
  PIN o[246]
    DIRECTION OUTPUT ;
    USE SIGNAL ;
    PORT
      LAYER M4 ;
        RECT  0 55.44 0.084 55.464 ;
    END
  END o[246]
  PIN o[247]
    DIRECTION OUTPUT ;
    USE SIGNAL ;
    PORT
      LAYER M4 ;
        RECT  0 55.536 0.084 55.56 ;
    END
  END o[247]
  PIN o[248]
    DIRECTION OUTPUT ;
    USE SIGNAL ;
    PORT
      LAYER M4 ;
        RECT  0 55.632 0.084 55.656 ;
    END
  END o[248]
  PIN o[249]
    DIRECTION OUTPUT ;
    USE SIGNAL ;
    PORT
      LAYER M4 ;
        RECT  0 55.728 0.084 55.752 ;
    END
  END o[249]
  PIN o[24]
    DIRECTION OUTPUT ;
    USE SIGNAL ;
    PORT
      LAYER M4 ;
        RECT  0 36.432 0.084 36.456 ;
    END
  END o[24]
  PIN o[250]
    DIRECTION OUTPUT ;
    USE SIGNAL ;
    PORT
      LAYER M4 ;
        RECT  0 55.824 0.084 55.848 ;
    END
  END o[250]
  PIN o[251]
    DIRECTION OUTPUT ;
    USE SIGNAL ;
    PORT
      LAYER M4 ;
        RECT  0 55.92 0.084 55.944 ;
    END
  END o[251]
  PIN o[252]
    DIRECTION OUTPUT ;
    USE SIGNAL ;
    PORT
      LAYER M4 ;
        RECT  0 56.016 0.084 56.04 ;
    END
  END o[252]
  PIN o[253]
    DIRECTION OUTPUT ;
    USE SIGNAL ;
    PORT
      LAYER M4 ;
        RECT  0 56.112 0.084 56.136 ;
    END
  END o[253]
  PIN o[254]
    DIRECTION OUTPUT ;
    USE SIGNAL ;
    PORT
      LAYER M4 ;
        RECT  0 56.208 0.084 56.232 ;
    END
  END o[254]
  PIN o[255]
    DIRECTION OUTPUT ;
    USE SIGNAL ;
    PORT
      LAYER M4 ;
        RECT  0 56.304 0.084 56.328 ;
    END
  END o[255]
  PIN o[256]
    DIRECTION OUTPUT ;
    USE SIGNAL ;
    PORT
      LAYER M4 ;
        RECT  0 31.536 0.084 31.56 ;
    END
  END o[256]
  PIN o[257]
    DIRECTION OUTPUT ;
    USE SIGNAL ;
    PORT
      LAYER M4 ;
        RECT  0 31.632 0.084 31.656 ;
    END
  END o[257]
  PIN o[258]
    DIRECTION OUTPUT ;
    USE SIGNAL ;
    PORT
      LAYER M4 ;
        RECT  0 31.728 0.084 31.752 ;
    END
  END o[258]
  PIN o[259]
    DIRECTION OUTPUT ;
    USE SIGNAL ;
    PORT
      LAYER M4 ;
        RECT  0 31.824 0.084 31.848 ;
    END
  END o[259]
  PIN o[25]
    DIRECTION OUTPUT ;
    USE SIGNAL ;
    PORT
      LAYER M4 ;
        RECT  0 36.528 0.084 36.552 ;
    END
  END o[25]
  PIN o[260]
    DIRECTION OUTPUT ;
    USE SIGNAL ;
    PORT
      LAYER M4 ;
        RECT  0 31.92 0.084 31.944 ;
    END
  END o[260]
  PIN o[261]
    DIRECTION OUTPUT ;
    USE SIGNAL ;
    PORT
      LAYER M4 ;
        RECT  0 32.016 0.084 32.04 ;
    END
  END o[261]
  PIN o[262]
    DIRECTION OUTPUT ;
    USE SIGNAL ;
    PORT
      LAYER M4 ;
        RECT  0 32.112 0.084 32.136 ;
    END
  END o[262]
  PIN o[263]
    DIRECTION OUTPUT ;
    USE SIGNAL ;
    PORT
      LAYER M4 ;
        RECT  0 32.208 0.084 32.232 ;
    END
  END o[263]
  PIN o[264]
    DIRECTION OUTPUT ;
    USE SIGNAL ;
    PORT
      LAYER M4 ;
        RECT  0 32.304 0.084 32.328 ;
    END
  END o[264]
  PIN o[265]
    DIRECTION OUTPUT ;
    USE SIGNAL ;
    PORT
      LAYER M4 ;
        RECT  0 32.4 0.084 32.424 ;
    END
  END o[265]
  PIN o[266]
    DIRECTION OUTPUT ;
    USE SIGNAL ;
    PORT
      LAYER M4 ;
        RECT  0 32.496 0.084 32.52 ;
    END
  END o[266]
  PIN o[267]
    DIRECTION OUTPUT ;
    USE SIGNAL ;
    PORT
      LAYER M4 ;
        RECT  0 32.592 0.084 32.616 ;
    END
  END o[267]
  PIN o[268]
    DIRECTION OUTPUT ;
    USE SIGNAL ;
    PORT
      LAYER M4 ;
        RECT  0 32.688 0.084 32.712 ;
    END
  END o[268]
  PIN o[269]
    DIRECTION OUTPUT ;
    USE SIGNAL ;
    PORT
      LAYER M4 ;
        RECT  0 32.784 0.084 32.808 ;
    END
  END o[269]
  PIN o[26]
    DIRECTION OUTPUT ;
    USE SIGNAL ;
    PORT
      LAYER M4 ;
        RECT  0 36.624 0.084 36.648 ;
    END
  END o[26]
  PIN o[270]
    DIRECTION OUTPUT ;
    USE SIGNAL ;
    PORT
      LAYER M4 ;
        RECT  0 32.88 0.084 32.904 ;
    END
  END o[270]
  PIN o[271]
    DIRECTION OUTPUT ;
    USE SIGNAL ;
    PORT
      LAYER M4 ;
        RECT  0 32.976 0.084 33 ;
    END
  END o[271]
  PIN o[272]
    DIRECTION OUTPUT ;
    USE SIGNAL ;
    PORT
      LAYER M4 ;
        RECT  0 33.072 0.084 33.096 ;
    END
  END o[272]
  PIN o[273]
    DIRECTION OUTPUT ;
    USE SIGNAL ;
    PORT
      LAYER M4 ;
        RECT  0 33.168 0.084 33.192 ;
    END
  END o[273]
  PIN o[274]
    DIRECTION OUTPUT ;
    USE SIGNAL ;
    PORT
      LAYER M4 ;
        RECT  0 33.264 0.084 33.288 ;
    END
  END o[274]
  PIN o[275]
    DIRECTION OUTPUT ;
    USE SIGNAL ;
    PORT
      LAYER M4 ;
        RECT  0 33.36 0.084 33.384 ;
    END
  END o[275]
  PIN o[276]
    DIRECTION OUTPUT ;
    USE SIGNAL ;
    PORT
      LAYER M4 ;
        RECT  0 33.456 0.084 33.48 ;
    END
  END o[276]
  PIN o[277]
    DIRECTION OUTPUT ;
    USE SIGNAL ;
    PORT
      LAYER M4 ;
        RECT  0 33.552 0.084 33.576 ;
    END
  END o[277]
  PIN o[278]
    DIRECTION OUTPUT ;
    USE SIGNAL ;
    PORT
      LAYER M4 ;
        RECT  0 33.648 0.084 33.672 ;
    END
  END o[278]
  PIN o[279]
    DIRECTION OUTPUT ;
    USE SIGNAL ;
    PORT
      LAYER M4 ;
        RECT  0 33.744 0.084 33.768 ;
    END
  END o[279]
  PIN o[27]
    DIRECTION OUTPUT ;
    USE SIGNAL ;
    PORT
      LAYER M4 ;
        RECT  0 36.72 0.084 36.744 ;
    END
  END o[27]
  PIN o[280]
    DIRECTION OUTPUT ;
    USE SIGNAL ;
    PORT
      LAYER M4 ;
        RECT  0 33.84 0.084 33.864 ;
    END
  END o[280]
  PIN o[281]
    DIRECTION OUTPUT ;
    USE SIGNAL ;
    PORT
      LAYER M4 ;
        RECT  0 33.936 0.084 33.96 ;
    END
  END o[281]
  PIN o[282]
    DIRECTION OUTPUT ;
    USE SIGNAL ;
    PORT
      LAYER M4 ;
        RECT  0 34.032 0.084 34.056 ;
    END
  END o[282]
  PIN o[28]
    DIRECTION OUTPUT ;
    USE SIGNAL ;
    PORT
      LAYER M4 ;
        RECT  0 36.816 0.084 36.84 ;
    END
  END o[28]
  PIN o[29]
    DIRECTION OUTPUT ;
    USE SIGNAL ;
    PORT
      LAYER M4 ;
        RECT  0 36.912 0.084 36.936 ;
    END
  END o[29]
  PIN o[2]
    DIRECTION OUTPUT ;
    USE SIGNAL ;
    PORT
      LAYER M4 ;
        RECT  0 34.32 0.084 34.344 ;
    END
  END o[2]
  PIN o[30]
    DIRECTION OUTPUT ;
    USE SIGNAL ;
    PORT
      LAYER M4 ;
        RECT  0 37.008 0.084 37.032 ;
    END
  END o[30]
  PIN o[31]
    DIRECTION OUTPUT ;
    USE SIGNAL ;
    PORT
      LAYER M4 ;
        RECT  0 37.104 0.084 37.128 ;
    END
  END o[31]
  PIN o[32]
    DIRECTION OUTPUT ;
    USE SIGNAL ;
    PORT
      LAYER M4 ;
        RECT  0 37.2 0.084 37.224 ;
    END
  END o[32]
  PIN o[33]
    DIRECTION OUTPUT ;
    USE SIGNAL ;
    PORT
      LAYER M4 ;
        RECT  0 37.296 0.084 37.32 ;
    END
  END o[33]
  PIN o[34]
    DIRECTION OUTPUT ;
    USE SIGNAL ;
    PORT
      LAYER M4 ;
        RECT  0 37.392 0.084 37.416 ;
    END
  END o[34]
  PIN o[35]
    DIRECTION OUTPUT ;
    USE SIGNAL ;
    PORT
      LAYER M4 ;
        RECT  0 37.488 0.084 37.512 ;
    END
  END o[35]
  PIN o[36]
    DIRECTION OUTPUT ;
    USE SIGNAL ;
    PORT
      LAYER M4 ;
        RECT  0 37.584 0.084 37.608 ;
    END
  END o[36]
  PIN o[37]
    DIRECTION OUTPUT ;
    USE SIGNAL ;
    PORT
      LAYER M4 ;
        RECT  0 37.68 0.084 37.704 ;
    END
  END o[37]
  PIN o[38]
    DIRECTION OUTPUT ;
    USE SIGNAL ;
    PORT
      LAYER M4 ;
        RECT  0 37.776 0.084 37.8 ;
    END
  END o[38]
  PIN o[39]
    DIRECTION OUTPUT ;
    USE SIGNAL ;
    PORT
      LAYER M4 ;
        RECT  0 37.872 0.084 37.896 ;
    END
  END o[39]
  PIN o[3]
    DIRECTION OUTPUT ;
    USE SIGNAL ;
    PORT
      LAYER M4 ;
        RECT  0 34.416 0.084 34.44 ;
    END
  END o[3]
  PIN o[40]
    DIRECTION OUTPUT ;
    USE SIGNAL ;
    PORT
      LAYER M4 ;
        RECT  0 37.968 0.084 37.992 ;
    END
  END o[40]
  PIN o[41]
    DIRECTION OUTPUT ;
    USE SIGNAL ;
    PORT
      LAYER M4 ;
        RECT  0 38.064 0.084 38.088 ;
    END
  END o[41]
  PIN o[42]
    DIRECTION OUTPUT ;
    USE SIGNAL ;
    PORT
      LAYER M4 ;
        RECT  0 38.16 0.084 38.184 ;
    END
  END o[42]
  PIN o[43]
    DIRECTION OUTPUT ;
    USE SIGNAL ;
    PORT
      LAYER M4 ;
        RECT  0 38.256 0.084 38.28 ;
    END
  END o[43]
  PIN o[44]
    DIRECTION OUTPUT ;
    USE SIGNAL ;
    PORT
      LAYER M4 ;
        RECT  0 38.352 0.084 38.376 ;
    END
  END o[44]
  PIN o[45]
    DIRECTION OUTPUT ;
    USE SIGNAL ;
    PORT
      LAYER M4 ;
        RECT  0 38.448 0.084 38.472 ;
    END
  END o[45]
  PIN o[46]
    DIRECTION OUTPUT ;
    USE SIGNAL ;
    PORT
      LAYER M4 ;
        RECT  0 38.544 0.084 38.568 ;
    END
  END o[46]
  PIN o[47]
    DIRECTION OUTPUT ;
    USE SIGNAL ;
    PORT
      LAYER M4 ;
        RECT  0 38.64 0.084 38.664 ;
    END
  END o[47]
  PIN o[48]
    DIRECTION OUTPUT ;
    USE SIGNAL ;
    PORT
      LAYER M4 ;
        RECT  0 38.736 0.084 38.76 ;
    END
  END o[48]
  PIN o[49]
    DIRECTION OUTPUT ;
    USE SIGNAL ;
    PORT
      LAYER M4 ;
        RECT  0 38.832 0.084 38.856 ;
    END
  END o[49]
  PIN o[4]
    DIRECTION OUTPUT ;
    USE SIGNAL ;
    PORT
      LAYER M4 ;
        RECT  0 34.512 0.084 34.536 ;
    END
  END o[4]
  PIN o[50]
    DIRECTION OUTPUT ;
    USE SIGNAL ;
    PORT
      LAYER M4 ;
        RECT  0 38.928 0.084 38.952 ;
    END
  END o[50]
  PIN o[51]
    DIRECTION OUTPUT ;
    USE SIGNAL ;
    PORT
      LAYER M4 ;
        RECT  0 39.024 0.084 39.048 ;
    END
  END o[51]
  PIN o[52]
    DIRECTION OUTPUT ;
    USE SIGNAL ;
    PORT
      LAYER M4 ;
        RECT  0 39.12 0.084 39.144 ;
    END
  END o[52]
  PIN o[53]
    DIRECTION OUTPUT ;
    USE SIGNAL ;
    PORT
      LAYER M4 ;
        RECT  0 39.216 0.084 39.24 ;
    END
  END o[53]
  PIN o[54]
    DIRECTION OUTPUT ;
    USE SIGNAL ;
    PORT
      LAYER M4 ;
        RECT  0 39.312 0.084 39.336 ;
    END
  END o[54]
  PIN o[55]
    DIRECTION OUTPUT ;
    USE SIGNAL ;
    PORT
      LAYER M4 ;
        RECT  0 39.408 0.084 39.432 ;
    END
  END o[55]
  PIN o[56]
    DIRECTION OUTPUT ;
    USE SIGNAL ;
    PORT
      LAYER M4 ;
        RECT  0 39.504 0.084 39.528 ;
    END
  END o[56]
  PIN o[57]
    DIRECTION OUTPUT ;
    USE SIGNAL ;
    PORT
      LAYER M4 ;
        RECT  0 39.6 0.084 39.624 ;
    END
  END o[57]
  PIN o[58]
    DIRECTION OUTPUT ;
    USE SIGNAL ;
    PORT
      LAYER M4 ;
        RECT  0 39.696 0.084 39.72 ;
    END
  END o[58]
  PIN o[59]
    DIRECTION OUTPUT ;
    USE SIGNAL ;
    PORT
      LAYER M4 ;
        RECT  0 39.792 0.084 39.816 ;
    END
  END o[59]
  PIN o[5]
    DIRECTION OUTPUT ;
    USE SIGNAL ;
    PORT
      LAYER M4 ;
        RECT  0 34.608 0.084 34.632 ;
    END
  END o[5]
  PIN o[60]
    DIRECTION OUTPUT ;
    USE SIGNAL ;
    PORT
      LAYER M4 ;
        RECT  0 39.888 0.084 39.912 ;
    END
  END o[60]
  PIN o[61]
    DIRECTION OUTPUT ;
    USE SIGNAL ;
    PORT
      LAYER M4 ;
        RECT  0 39.984 0.084 40.008 ;
    END
  END o[61]
  PIN o[62]
    DIRECTION OUTPUT ;
    USE SIGNAL ;
    PORT
      LAYER M4 ;
        RECT  0 40.08 0.084 40.104 ;
    END
  END o[62]
  PIN o[63]
    DIRECTION OUTPUT ;
    USE SIGNAL ;
    PORT
      LAYER M4 ;
        RECT  0 40.176 0.084 40.2 ;
    END
  END o[63]
  PIN o[64]
    DIRECTION OUTPUT ;
    USE SIGNAL ;
    PORT
      LAYER M4 ;
        RECT  0 47.184 0.084 47.208 ;
    END
  END o[64]
  PIN o[65]
    DIRECTION OUTPUT ;
    USE SIGNAL ;
    PORT
      LAYER M4 ;
        RECT  0 47.28 0.084 47.304 ;
    END
  END o[65]
  PIN o[66]
    DIRECTION OUTPUT ;
    USE SIGNAL ;
    PORT
      LAYER M4 ;
        RECT  0 47.376 0.084 47.4 ;
    END
  END o[66]
  PIN o[67]
    DIRECTION OUTPUT ;
    USE SIGNAL ;
    PORT
      LAYER M4 ;
        RECT  0 47.472 0.084 47.496 ;
    END
  END o[67]
  PIN o[68]
    DIRECTION OUTPUT ;
    USE SIGNAL ;
    PORT
      LAYER M4 ;
        RECT  0 47.568 0.084 47.592 ;
    END
  END o[68]
  PIN o[69]
    DIRECTION OUTPUT ;
    USE SIGNAL ;
    PORT
      LAYER M4 ;
        RECT  0 47.664 0.084 47.688 ;
    END
  END o[69]
  PIN o[6]
    DIRECTION OUTPUT ;
    USE SIGNAL ;
    PORT
      LAYER M4 ;
        RECT  0 34.704 0.084 34.728 ;
    END
  END o[6]
  PIN o[70]
    DIRECTION OUTPUT ;
    USE SIGNAL ;
    PORT
      LAYER M4 ;
        RECT  0 47.76 0.084 47.784 ;
    END
  END o[70]
  PIN o[71]
    DIRECTION OUTPUT ;
    USE SIGNAL ;
    PORT
      LAYER M4 ;
        RECT  0 47.856 0.084 47.88 ;
    END
  END o[71]
  PIN o[72]
    DIRECTION OUTPUT ;
    USE SIGNAL ;
    PORT
      LAYER M4 ;
        RECT  0 47.952 0.084 47.976 ;
    END
  END o[72]
  PIN o[73]
    DIRECTION OUTPUT ;
    USE SIGNAL ;
    PORT
      LAYER M4 ;
        RECT  0 48.048 0.084 48.072 ;
    END
  END o[73]
  PIN o[74]
    DIRECTION OUTPUT ;
    USE SIGNAL ;
    PORT
      LAYER M4 ;
        RECT  0 48.144 0.084 48.168 ;
    END
  END o[74]
  PIN o[75]
    DIRECTION OUTPUT ;
    USE SIGNAL ;
    PORT
      LAYER M4 ;
        RECT  0 48.24 0.084 48.264 ;
    END
  END o[75]
  PIN o[76]
    DIRECTION OUTPUT ;
    USE SIGNAL ;
    PORT
      LAYER M4 ;
        RECT  0 48.336 0.084 48.36 ;
    END
  END o[76]
  PIN o[77]
    DIRECTION OUTPUT ;
    USE SIGNAL ;
    PORT
      LAYER M4 ;
        RECT  0 48.432 0.084 48.456 ;
    END
  END o[77]
  PIN o[78]
    DIRECTION OUTPUT ;
    USE SIGNAL ;
    PORT
      LAYER M4 ;
        RECT  0 48.528 0.084 48.552 ;
    END
  END o[78]
  PIN o[79]
    DIRECTION OUTPUT ;
    USE SIGNAL ;
    PORT
      LAYER M4 ;
        RECT  0 48.624 0.084 48.648 ;
    END
  END o[79]
  PIN o[7]
    DIRECTION OUTPUT ;
    USE SIGNAL ;
    PORT
      LAYER M4 ;
        RECT  0 34.8 0.084 34.824 ;
    END
  END o[7]
  PIN o[80]
    DIRECTION OUTPUT ;
    USE SIGNAL ;
    PORT
      LAYER M4 ;
        RECT  0 48.72 0.084 48.744 ;
    END
  END o[80]
  PIN o[81]
    DIRECTION OUTPUT ;
    USE SIGNAL ;
    PORT
      LAYER M4 ;
        RECT  0 48.816 0.084 48.84 ;
    END
  END o[81]
  PIN o[82]
    DIRECTION OUTPUT ;
    USE SIGNAL ;
    PORT
      LAYER M4 ;
        RECT  0 48.912 0.084 48.936 ;
    END
  END o[82]
  PIN o[83]
    DIRECTION OUTPUT ;
    USE SIGNAL ;
    PORT
      LAYER M4 ;
        RECT  0 49.008 0.084 49.032 ;
    END
  END o[83]
  PIN o[84]
    DIRECTION OUTPUT ;
    USE SIGNAL ;
    PORT
      LAYER M4 ;
        RECT  0 49.104 0.084 49.128 ;
    END
  END o[84]
  PIN o[85]
    DIRECTION OUTPUT ;
    USE SIGNAL ;
    PORT
      LAYER M4 ;
        RECT  0 49.2 0.084 49.224 ;
    END
  END o[85]
  PIN o[86]
    DIRECTION OUTPUT ;
    USE SIGNAL ;
    PORT
      LAYER M4 ;
        RECT  0 49.296 0.084 49.32 ;
    END
  END o[86]
  PIN o[87]
    DIRECTION OUTPUT ;
    USE SIGNAL ;
    PORT
      LAYER M4 ;
        RECT  0 49.392 0.084 49.416 ;
    END
  END o[87]
  PIN o[88]
    DIRECTION OUTPUT ;
    USE SIGNAL ;
    PORT
      LAYER M4 ;
        RECT  0 49.488 0.084 49.512 ;
    END
  END o[88]
  PIN o[89]
    DIRECTION OUTPUT ;
    USE SIGNAL ;
    PORT
      LAYER M4 ;
        RECT  0 49.584 0.084 49.608 ;
    END
  END o[89]
  PIN o[8]
    DIRECTION OUTPUT ;
    USE SIGNAL ;
    PORT
      LAYER M4 ;
        RECT  0 34.896 0.084 34.92 ;
    END
  END o[8]
  PIN o[90]
    DIRECTION OUTPUT ;
    USE SIGNAL ;
    PORT
      LAYER M4 ;
        RECT  0 49.68 0.084 49.704 ;
    END
  END o[90]
  PIN o[91]
    DIRECTION OUTPUT ;
    USE SIGNAL ;
    PORT
      LAYER M4 ;
        RECT  0 49.776 0.084 49.8 ;
    END
  END o[91]
  PIN o[92]
    DIRECTION OUTPUT ;
    USE SIGNAL ;
    PORT
      LAYER M4 ;
        RECT  0 49.872 0.084 49.896 ;
    END
  END o[92]
  PIN o[93]
    DIRECTION OUTPUT ;
    USE SIGNAL ;
    PORT
      LAYER M4 ;
        RECT  0 49.968 0.084 49.992 ;
    END
  END o[93]
  PIN o[94]
    DIRECTION OUTPUT ;
    USE SIGNAL ;
    PORT
      LAYER M4 ;
        RECT  0 50.064 0.084 50.088 ;
    END
  END o[94]
  PIN o[95]
    DIRECTION OUTPUT ;
    USE SIGNAL ;
    PORT
      LAYER M4 ;
        RECT  0 50.16 0.084 50.184 ;
    END
  END o[95]
  PIN o[96]
    DIRECTION OUTPUT ;
    USE SIGNAL ;
    PORT
      LAYER M4 ;
        RECT  0 41.04 0.084 41.064 ;
    END
  END o[96]
  PIN o[97]
    DIRECTION OUTPUT ;
    USE SIGNAL ;
    PORT
      LAYER M4 ;
        RECT  0 41.136 0.084 41.16 ;
    END
  END o[97]
  PIN o[98]
    DIRECTION OUTPUT ;
    USE SIGNAL ;
    PORT
      LAYER M4 ;
        RECT  0 41.232 0.084 41.256 ;
    END
  END o[98]
  PIN o[99]
    DIRECTION OUTPUT ;
    USE SIGNAL ;
    PORT
      LAYER M4 ;
        RECT  0 41.328 0.084 41.352 ;
    END
  END o[99]
  PIN o[9]
    DIRECTION OUTPUT ;
    USE SIGNAL ;
    PORT
      LAYER M4 ;
        RECT  0 34.992 0.084 35.016 ;
    END
  END o[9]
  PIN rs
    DIRECTION INPUT ;
    USE SIGNAL ;
    PORT
      LAYER M5 ;
        RECT  9.936 60.396 9.96 60.48 ;
    END
  END rs
  PIN VDD
    DIRECTION INOUT ;
    USE POWER ;
    PORT
      LAYER M5 ;
        RECT  18.792 2.151 18.912 58.329 ;
        RECT  13.392 2.151 13.512 58.329 ;
        RECT  7.992 2.151 8.112 58.329 ;
        RECT  2.592 2.151 2.712 58.329 ;
    END
  END VDD
  PIN VSS
    DIRECTION INOUT ;
    USE GROUND ;
    PORT
      LAYER M5 ;
        RECT  18.6 2.137 18.72 58.343 ;
        RECT  13.2 2.137 13.32 58.343 ;
        RECT  7.8 2.137 7.92 58.343 ;
        RECT  2.4 2.137 2.52 58.343 ;
    END
  END VSS
  OBS
    LAYER RVTN ;
     RECT  2.16 2.16 21.6 2.295 ;
     RECT  2.16 2.565 21.6 2.835 ;
     RECT  2.16 3.105 21.6 3.375 ;
     RECT  2.16 3.645 21.6 3.915 ;
     RECT  2.16 4.185 21.6 4.455 ;
     RECT  2.16 4.725 21.6 4.995 ;
     RECT  2.16 5.265 21.6 5.535 ;
     RECT  2.16 5.805 21.6 6.075 ;
     RECT  2.16 6.345 21.6 6.615 ;
     RECT  2.16 6.885 21.6 7.155 ;
     RECT  2.16 7.425 21.6 7.695 ;
     RECT  2.16 7.965 21.6 8.235 ;
     RECT  2.16 8.505 21.6 8.775 ;
     RECT  2.16 9.045 21.6 9.315 ;
     RECT  2.16 9.585 21.6 9.855 ;
     RECT  2.16 10.125 21.6 10.395 ;
     RECT  2.16 10.665 21.6 10.935 ;
     RECT  2.16 11.205 21.6 11.475 ;
     RECT  2.16 11.745 21.6 12.015 ;
     RECT  2.16 12.285 21.6 12.555 ;
     RECT  2.16 12.825 21.6 13.095 ;
     RECT  2.16 13.365 21.6 13.635 ;
     RECT  2.16 13.905 21.6 14.175 ;
     RECT  2.16 14.445 21.6 14.715 ;
     RECT  2.16 14.985 21.6 15.255 ;
     RECT  2.16 15.525 21.6 15.795 ;
     RECT  2.16 16.065 21.6 16.335 ;
     RECT  2.16 16.605 21.6 16.875 ;
     RECT  2.16 17.145 21.6 17.415 ;
     RECT  2.16 17.685 21.6 17.955 ;
     RECT  2.16 18.225 21.6 18.495 ;
     RECT  2.16 18.765 21.6 19.035 ;
     RECT  2.16 19.305 21.6 19.575 ;
     RECT  2.16 19.845 21.6 20.115 ;
     RECT  2.16 20.385 21.6 20.655 ;
     RECT  2.16 20.925 21.6 21.195 ;
     RECT  2.16 21.465 21.6 21.735 ;
     RECT  2.16 22.005 21.6 22.275 ;
     RECT  2.16 22.545 21.6 22.815 ;
     RECT  2.16 23.085 21.6 23.355 ;
     RECT  2.16 23.625 21.6 23.895 ;
     RECT  2.16 24.165 21.6 24.435 ;
     RECT  2.16 24.705 21.6 24.975 ;
     RECT  2.16 25.245 21.6 25.515 ;
     RECT  2.16 25.785 21.6 26.055 ;
     RECT  2.16 26.325 21.6 26.595 ;
     RECT  2.16 26.865 21.6 27.135 ;
     RECT  2.16 27.405 21.6 27.675 ;
     RECT  2.16 27.945 21.6 28.215 ;
     RECT  2.16 28.485 21.6 28.755 ;
     RECT  2.16 29.025 21.6 29.295 ;
     RECT  2.16 29.565 21.6 29.835 ;
     RECT  2.16 30.105 21.6 30.375 ;
     RECT  2.16 30.645 21.6 30.915 ;
     RECT  2.16 31.185 21.6 31.455 ;
     RECT  2.16 31.725 21.6 31.995 ;
     RECT  2.16 32.265 21.6 32.535 ;
     RECT  2.16 32.805 21.6 33.075 ;
     RECT  2.16 33.345 21.6 33.615 ;
     RECT  2.16 33.885 21.6 34.155 ;
     RECT  2.16 34.425 21.6 34.695 ;
     RECT  2.16 34.965 21.6 35.235 ;
     RECT  2.16 35.505 21.6 35.775 ;
     RECT  2.16 36.045 21.6 36.315 ;
     RECT  2.16 36.585 21.6 36.855 ;
     RECT  2.16 37.125 21.6 37.395 ;
     RECT  2.16 37.665 21.6 37.935 ;
     RECT  2.16 38.205 21.6 38.475 ;
     RECT  2.16 38.745 21.6 39.015 ;
     RECT  2.16 39.285 21.6 39.555 ;
     RECT  2.16 39.825 21.6 40.095 ;
     RECT  2.16 40.365 21.6 40.635 ;
     RECT  2.16 40.905 21.6 41.175 ;
     RECT  2.16 41.445 21.6 41.715 ;
     RECT  2.16 41.985 21.6 42.255 ;
     RECT  2.16 42.525 21.6 42.795 ;
     RECT  2.16 43.065 21.6 43.335 ;
     RECT  2.16 43.605 21.6 43.875 ;
     RECT  2.16 44.145 21.6 44.415 ;
     RECT  2.16 44.685 21.6 44.955 ;
     RECT  2.16 45.225 21.6 45.495 ;
     RECT  2.16 45.765 21.6 46.035 ;
     RECT  2.16 46.305 21.6 46.575 ;
     RECT  2.16 46.845 21.6 47.115 ;
     RECT  2.16 47.385 21.6 47.655 ;
     RECT  2.16 47.925 21.6 48.195 ;
     RECT  2.16 48.465 21.6 48.735 ;
     RECT  2.16 49.005 21.6 49.275 ;
     RECT  2.16 49.545 21.6 49.815 ;
     RECT  2.16 50.085 21.6 50.355 ;
     RECT  2.16 50.625 21.6 50.895 ;
     RECT  2.16 51.165 21.6 51.435 ;
     RECT  2.16 51.705 21.6 51.975 ;
     RECT  2.16 52.245 21.6 52.515 ;
     RECT  2.16 52.785 21.6 53.055 ;
     RECT  2.16 53.325 21.6 53.595 ;
     RECT  2.16 53.865 21.6 54.135 ;
     RECT  2.16 54.405 21.6 54.675 ;
     RECT  2.16 54.945 21.6 55.215 ;
     RECT  2.16 55.485 21.6 55.755 ;
     RECT  2.16 56.025 21.6 56.295 ;
     RECT  2.16 56.565 21.6 56.835 ;
     RECT  2.16 57.105 21.6 57.375 ;
     RECT  2.16 57.645 21.6 57.915 ;
     RECT  2.16 58.185 21.6 58.32 ;
    LAYER RVTP ;
     RECT  2.16 2.295 21.6 2.565 ;
     RECT  2.16 2.835 21.6 3.105 ;
     RECT  2.16 3.375 21.6 3.645 ;
     RECT  2.16 3.915 21.6 4.185 ;
     RECT  2.16 4.455 21.6 4.725 ;
     RECT  2.16 4.995 21.6 5.265 ;
     RECT  2.16 5.535 21.6 5.805 ;
     RECT  2.16 6.075 21.6 6.345 ;
     RECT  2.16 6.615 21.6 6.885 ;
     RECT  2.16 7.155 21.6 7.425 ;
     RECT  2.16 7.695 21.6 7.965 ;
     RECT  2.16 8.235 21.6 8.505 ;
     RECT  2.16 8.775 21.6 9.045 ;
     RECT  2.16 9.315 21.6 9.585 ;
     RECT  2.16 9.855 21.6 10.125 ;
     RECT  2.16 10.395 21.6 10.665 ;
     RECT  2.16 10.935 21.6 11.205 ;
     RECT  2.16 11.475 21.6 11.745 ;
     RECT  2.16 12.015 21.6 12.285 ;
     RECT  2.16 12.555 21.6 12.825 ;
     RECT  2.16 13.095 21.6 13.365 ;
     RECT  2.16 13.635 21.6 13.905 ;
     RECT  2.16 14.175 21.6 14.445 ;
     RECT  2.16 14.715 21.6 14.985 ;
     RECT  2.16 15.255 21.6 15.525 ;
     RECT  2.16 15.795 21.6 16.065 ;
     RECT  2.16 16.335 21.6 16.605 ;
     RECT  2.16 16.875 21.6 17.145 ;
     RECT  2.16 17.415 21.6 17.685 ;
     RECT  2.16 17.955 21.6 18.225 ;
     RECT  2.16 18.495 21.6 18.765 ;
     RECT  2.16 19.035 21.6 19.305 ;
     RECT  2.16 19.575 21.6 19.845 ;
     RECT  2.16 20.115 21.6 20.385 ;
     RECT  2.16 20.655 21.6 20.925 ;
     RECT  2.16 21.195 21.6 21.465 ;
     RECT  2.16 21.735 21.6 22.005 ;
     RECT  2.16 22.275 21.6 22.545 ;
     RECT  2.16 22.815 21.6 23.085 ;
     RECT  2.16 23.355 21.6 23.625 ;
     RECT  2.16 23.895 21.6 24.165 ;
     RECT  2.16 24.435 21.6 24.705 ;
     RECT  2.16 24.975 21.6 25.245 ;
     RECT  2.16 25.515 21.6 25.785 ;
     RECT  2.16 26.055 21.6 26.325 ;
     RECT  2.16 26.595 21.6 26.865 ;
     RECT  2.16 27.135 21.6 27.405 ;
     RECT  2.16 27.675 21.6 27.945 ;
     RECT  2.16 28.215 21.6 28.485 ;
     RECT  2.16 28.755 21.6 29.025 ;
     RECT  2.16 29.295 21.6 29.565 ;
     RECT  2.16 29.835 21.6 30.105 ;
     RECT  2.16 30.375 21.6 30.645 ;
     RECT  2.16 30.915 21.6 31.185 ;
     RECT  2.16 31.455 21.6 31.725 ;
     RECT  2.16 31.995 21.6 32.265 ;
     RECT  2.16 32.535 21.6 32.805 ;
     RECT  2.16 33.075 21.6 33.345 ;
     RECT  2.16 33.615 21.6 33.885 ;
     RECT  2.16 34.155 21.6 34.425 ;
     RECT  2.16 34.695 21.6 34.965 ;
     RECT  2.16 35.235 21.6 35.505 ;
     RECT  2.16 35.775 21.6 36.045 ;
     RECT  2.16 36.315 21.6 36.585 ;
     RECT  2.16 36.855 21.6 37.125 ;
     RECT  2.16 37.395 21.6 37.665 ;
     RECT  2.16 37.935 21.6 38.205 ;
     RECT  2.16 38.475 21.6 38.745 ;
     RECT  2.16 39.015 21.6 39.285 ;
     RECT  2.16 39.555 21.6 39.825 ;
     RECT  2.16 40.095 21.6 40.365 ;
     RECT  2.16 40.635 21.6 40.905 ;
     RECT  2.16 41.175 21.6 41.445 ;
     RECT  2.16 41.715 21.6 41.985 ;
     RECT  2.16 42.255 21.6 42.525 ;
     RECT  2.16 42.795 21.6 43.065 ;
     RECT  2.16 43.335 21.6 43.605 ;
     RECT  2.16 43.875 21.6 44.145 ;
     RECT  2.16 44.415 21.6 44.685 ;
     RECT  2.16 44.955 21.6 45.225 ;
     RECT  2.16 45.495 21.6 45.765 ;
     RECT  2.16 46.035 21.6 46.305 ;
     RECT  2.16 46.575 21.6 46.845 ;
     RECT  2.16 47.115 21.6 47.385 ;
     RECT  2.16 47.655 21.6 47.925 ;
     RECT  2.16 48.195 21.6 48.465 ;
     RECT  2.16 48.735 21.6 49.005 ;
     RECT  2.16 49.275 21.6 49.545 ;
     RECT  2.16 49.815 21.6 50.085 ;
     RECT  2.16 50.355 21.6 50.625 ;
     RECT  2.16 50.895 21.6 51.165 ;
     RECT  2.16 51.435 21.6 51.705 ;
     RECT  2.16 51.975 21.6 52.245 ;
     RECT  2.16 52.515 21.6 52.785 ;
     RECT  2.16 53.055 21.6 53.325 ;
     RECT  2.16 53.595 21.6 53.865 ;
     RECT  2.16 54.135 21.6 54.405 ;
     RECT  2.16 54.675 21.6 54.945 ;
     RECT  2.16 55.215 21.6 55.485 ;
     RECT  2.16 55.755 21.6 56.025 ;
     RECT  2.16 56.295 21.6 56.565 ;
     RECT  2.16 56.835 21.6 57.105 ;
     RECT  2.16 57.375 21.6 57.645 ;
     RECT  2.16 57.915 21.6 58.185 ;
    LAYER M1 ;
     RECT  2.16 2.151 21.6 58.329 ;
    LAYER M2 ;
     RECT  0.103 45.54 0.139 45.558 ;
     RECT  0.103 47.088 0.139 47.34 ;
     RECT  0.103 48.366 0.139 48.384 ;
     RECT  0.103 35.856 0.203 35.874 ;
     RECT  0.103 44.388 0.203 44.406 ;
     RECT  0.139 45.54 0.203 46.134 ;
     RECT  0.139 47.088 0.203 48.384 ;
     RECT  0.103 49.356 0.203 49.914 ;
     RECT  0.103 52.992 0.203 53.55 ;
     RECT  0.103 38.754 0.211 39.114 ;
     RECT  0.103 58.194 0.211 58.518 ;
     RECT  0.103 8.748 0.239 8.766 ;
     RECT  0.203 46.116 0.239 46.134 ;
     RECT  0.203 47.628 0.239 47.754 ;
     RECT  0.211 18.666 0.347 18.684 ;
     RECT  0.211 38.754 0.347 39.618 ;
     RECT  0.211 57.924 0.347 58.518 ;
     RECT  0.103 30.42 0.355 30.438 ;
     RECT  0.103 9.558 0.383 9.576 ;
     RECT  0.211 54.99 0.383 55.008 ;
     RECT  0.103 42.066 0.391 43.362 ;
     RECT  0.391 42.066 0.427 43.866 ;
     RECT  0.203 49.824 0.463 49.914 ;
     RECT  0.463 49.824 0.499 50.454 ;
     RECT  0.139 10.71 0.535 10.728 ;
     RECT  0.103 12.294 0.535 12.312 ;
     RECT  0.355 30.42 0.535 30.474 ;
     RECT  0.355 26.802 0.563 26.82 ;
     RECT  0.463 46.746 0.563 46.764 ;
     RECT  0.427 41.796 0.599 43.866 ;
     RECT  0.239 47.628 1.039 47.646 ;
     RECT  0.499 56.106 1.075 56.124 ;
     RECT  0.463 13.986 1.147 14.004 ;
     RECT  1.111 16.11 1.147 16.128 ;
     RECT  0.535 17.154 1.147 17.172 ;
     RECT  0.535 30.384 1.147 30.474 ;
     RECT  0.355 32.616 1.147 32.634 ;
     RECT  0.347 38.754 1.147 38.772 ;
     RECT  1.147 13.986 1.175 14.202 ;
     RECT  1.147 32.544 1.175 32.634 ;
     RECT  1.147 28.296 1.183 28.314 ;
     RECT  0.823 29.574 1.327 29.592 ;
     RECT  1.147 30.384 1.327 30.519 ;
     RECT  1.183 28.296 1.363 28.71 ;
     RECT  1.327 29.574 1.363 30.519 ;
     RECT  1.363 28.296 1.435 30.519 ;
     RECT  1.435 28.296 1.471 30.672 ;
     RECT  0.571 26.64 1.507 26.658 ;
     RECT  1.471 27.72 1.507 30.672 ;
     RECT  0.103 33.93 1.507 33.948 ;
     RECT  1.507 27.72 1.543 31.284 ;
     RECT  0.499 49.824 1.579 50.814 ;
     RECT  1.039 47.628 1.615 48.384 ;
     RECT  1.507 26.64 1.651 26.892 ;
     RECT  1.543 27.72 1.651 31.482 ;
     RECT  1.651 26.64 1.687 31.482 ;
     RECT  0.535 57.456 1.687 57.474 ;
     RECT  0.535 10.71 1.723 10.998 ;
     RECT  0.103 20.7 1.723 20.718 ;
     RECT  0.571 40.914 1.723 40.932 ;
     RECT  1.723 24.912 1.759 24.93 ;
     RECT  1.147 38.754 1.759 39.384 ;
     RECT  0.211 35.478 1.795 35.496 ;
     RECT  0.599 42.606 1.795 43.866 ;
     RECT  1.759 24.912 1.831 25.272 ;
     RECT  1.831 23.634 1.939 23.652 ;
     RECT  1.687 26.64 1.939 31.518 ;
     RECT  1.175 32.544 1.939 32.562 ;
     RECT  1.723 40.914 1.939 41.004 ;
     RECT  1.939 23.436 1.975 23.652 ;
     RECT  1.831 24.912 1.975 25.812 ;
     RECT  1.759 22.05 2.011 22.068 ;
     RECT  1.795 35.406 2.011 35.496 ;
     RECT  1.939 26.64 2.047 32.562 ;
     RECT  1.507 33.426 2.047 33.948 ;
     RECT  1.795 42.606 2.047 44.244 ;
     RECT  0.499 18.036 2.119 18.054 ;
     RECT  1.759 38.754 2.119 39.582 ;
     RECT  2.047 42.606 2.119 44.874 ;
     RECT  2.119 18.036 2.155 18.45 ;
     RECT  1.687 57.114 2.155 57.474 ;
     RECT  1.687 3.114 2.16 3.132 ;
     RECT  1.687 8.244 2.16 8.262 ;
     RECT  1.723 10.134 2.16 10.998 ;
     RECT  0.535 12.294 2.16 12.384 ;
     RECT  1.291 13.176 2.16 13.194 ;
     RECT  1.175 14.184 2.16 14.202 ;
     RECT  1.975 15.3 2.16 15.318 ;
     RECT  1.147 16.11 2.16 17.172 ;
     RECT  2.155 18.036 2.16 18.558 ;
     RECT  2.155 19.782 2.16 19.944 ;
     RECT  1.723 20.7 2.16 21.222 ;
     RECT  2.011 22.05 2.16 22.644 ;
     RECT  1.975 23.436 2.16 25.812 ;
     RECT  2.047 26.64 2.16 33.948 ;
     RECT  2.011 35.046 2.16 35.496 ;
     RECT  1.795 37.026 2.16 37.044 ;
     RECT  2.119 38.556 2.16 39.582 ;
     RECT  1.939 40.374 2.16 41.004 ;
     RECT  0.599 41.796 2.16 41.814 ;
     RECT  2.119 42.606 2.16 44.946 ;
     RECT  1.615 46.926 2.16 48.384 ;
     RECT  1.579 49.176 2.16 50.814 ;
     RECT  1.651 51.606 2.16 51.624 ;
     RECT  2.155 54.72 2.16 54.738 ;
     RECT  1.075 55.566 2.16 56.124 ;
     RECT  2.155 57.114 2.16 58.014 ;
     RECT  2.16 2.151 2.299 58.329 ;
     RECT  2.299 2.151 2.615 58.374 ;
     RECT  2.615 2.151 2.767 58.329 ;
     RECT  2.767 1.962 3.271 58.329 ;
     RECT  3.271 1.926 5.567 58.329 ;
     RECT  5.567 2.106 7.303 58.329 ;
     RECT  7.303 1.998 7.951 58.329 ;
     RECT  7.951 1.926 9.851 58.329 ;
     RECT  9.851 2.106 11.219 58.329 ;
     RECT  11.219 2.151 21.6 58.329 ;
    LAYER M3 ;
     RECT  2.304 1.291 2.322 1.387 ;
     RECT  2.304 1.387 2.862 1.483 ;
     RECT  2.304 1.483 3.402 1.579 ;
     RECT  2.304 1.579 3.654 1.675 ;
     RECT  1.692 1.675 3.654 1.957 ;
     RECT  7.956 1.921 7.974 1.993 ;
     RECT  1.692 1.957 4.338 2.029 ;
     RECT  5.544 1.921 5.562 2.029 ;
     RECT  7.308 1.993 8.334 2.065 ;
     RECT  1.692 2.029 5.562 2.101 ;
     RECT  7.308 2.065 8.91 2.101 ;
     RECT  9.828 1.921 9.846 2.101 ;
     RECT  1.692 2.101 5.814 2.191 ;
     RECT  11.196 2.101 11.214 2.219 ;
     RECT  7.308 2.101 10.242 2.227 ;
     RECT  7.236 2.227 10.242 2.299 ;
     RECT  1.692 2.191 6.102 2.335 ;
     RECT  6.876 2.299 10.89 2.335 ;
     RECT  13.215 2.143 13.305 2.413 ;
     RECT  18.615 2.143 18.705 2.413 ;
     RECT  0.324 2.155 0.342 2.491 ;
     RECT  0.216 2.491 0.342 2.669 ;
     RECT  1.692 2.335 10.89 3.137 ;
     RECT  2.268 3.137 10.89 3.181 ;
     RECT  2.268 3.181 11.25 3.335 ;
     RECT  0.324 2.669 0.342 3.629 ;
     RECT  2.304 3.335 11.25 3.983 ;
     RECT  13.215 2.413 13.497 4.423 ;
     RECT  2.304 3.983 10.89 4.801 ;
     RECT  11.772 3.991 11.79 4.801 ;
     RECT  0.144 3.787 0.162 4.891 ;
     RECT  2.304 4.801 11.79 4.891 ;
     RECT  0.144 4.891 0.234 4.939 ;
     RECT  2.268 4.891 11.79 5.495 ;
     RECT  0.144 4.939 0.342 5.837 ;
     RECT  0.144 5.837 0.162 6.029 ;
     RECT  1.152 5.899 1.17 6.029 ;
     RECT  2.304 5.495 11.79 6.421 ;
     RECT  2.268 6.421 11.79 6.449 ;
     RECT  2.268 6.449 11.466 7.051 ;
     RECT  1.728 7.051 11.466 7.079 ;
     RECT  12.564 4.423 13.497 7.147 ;
     RECT  12.564 7.147 13.77 7.357 ;
     RECT  0.324 7.531 0.342 7.627 ;
     RECT  0.216 7.627 0.342 7.723 ;
     RECT  0.144 7.723 0.342 7.997 ;
     RECT  1.728 7.079 11.286 8.239 ;
     RECT  0.324 7.997 0.342 8.731 ;
     RECT  0.216 8.731 0.342 8.743 ;
     RECT  12.564 7.357 13.914 8.779 ;
     RECT  0.108 8.743 0.342 9.553 ;
     RECT  0.108 9.553 0.378 9.677 ;
     RECT  0.108 9.677 0.342 9.869 ;
     RECT  0.108 9.869 0.126 10.705 ;
     RECT  0.108 10.705 0.162 10.829 ;
     RECT  0.144 10.829 0.162 10.925 ;
     RECT  0.54 10.975 0.558 11.501 ;
     RECT  0.324 11.851 0.342 12.289 ;
     RECT  0.108 12.289 0.342 12.361 ;
     RECT  0.108 12.361 0.558 12.653 ;
     RECT  1.692 8.239 11.286 12.763 ;
     RECT  1.62 12.763 11.286 13.171 ;
     RECT  0.108 12.653 0.342 13.325 ;
     RECT  12.42 8.779 13.914 13.441 ;
     RECT  1.296 13.171 11.286 13.819 ;
     RECT  0.18 13.325 0.342 13.981 ;
     RECT  1.188 13.819 11.286 13.981 ;
     RECT  12.24 13.441 13.914 13.981 ;
     RECT  0.18 13.981 13.914 14.207 ;
     RECT  0.18 14.207 0.486 14.813 ;
     RECT  0.432 14.813 0.486 15.547 ;
     RECT  0.216 15.547 0.486 15.691 ;
     RECT  0.144 15.691 0.486 16.105 ;
     RECT  1.296 14.207 13.914 16.105 ;
     RECT  0.144 16.105 13.914 18.187 ;
     RECT  0.108 18.187 13.914 20.723 ;
     RECT  0.144 20.723 13.914 21.437 ;
     RECT  0.216 21.437 13.914 21.533 ;
     RECT  0.432 21.533 13.914 22.411 ;
     RECT  0.324 22.411 13.914 22.541 ;
     RECT  0.432 22.541 13.914 23.323 ;
     RECT  0.396 23.323 13.914 23.467 ;
     RECT  0.324 23.467 13.914 23.707 ;
     RECT  0.18 23.707 13.914 23.885 ;
     RECT  0.324 23.885 13.914 24.461 ;
     RECT  0.396 24.461 13.914 25.387 ;
     RECT  0.144 25.387 13.914 25.565 ;
     RECT  0.396 25.565 13.914 26.779 ;
     RECT  0.396 26.779 13.95 26.797 ;
     RECT  0.36 26.797 13.95 27.019 ;
     RECT  0.324 27.019 13.95 27.115 ;
     RECT  0.144 27.115 13.95 27.293 ;
     RECT  0.36 27.293 13.95 28.459 ;
     RECT  0.108 28.459 13.95 29.029 ;
     RECT  0.108 29.029 14.67 30.443 ;
     RECT  0.36 30.443 14.67 30.479 ;
     RECT  0.396 30.479 14.67 30.605 ;
     RECT  14.652 30.605 14.67 31.523 ;
     RECT  0.396 30.605 13.914 31.627 ;
     RECT  0.324 31.627 13.914 31.675 ;
     RECT  0.144 31.675 13.914 31.853 ;
     RECT  0.324 31.853 13.914 32.299 ;
     RECT  0.324 32.299 14.058 32.459 ;
     RECT  0.324 32.459 13.914 33.835 ;
     RECT  0.252 33.835 13.914 33.925 ;
     RECT  0.108 33.925 13.914 34.445 ;
     RECT  0.144 34.445 13.914 34.861 ;
     RECT  0.144 34.861 14.598 34.925 ;
     RECT  0.144 34.925 14.454 35.195 ;
     RECT  0.144 35.195 13.914 35.851 ;
     RECT  0.108 35.851 13.914 35.888 ;
     RECT  0.144 35.888 13.914 37.421 ;
     RECT  0.396 37.421 13.914 38.347 ;
     RECT  0.108 38.347 13.914 39.119 ;
     RECT  0.18 39.119 13.914 39.979 ;
     RECT  0.144 39.979 13.914 40.157 ;
     RECT  0.396 40.157 13.914 41.803 ;
     RECT  0.144 41.803 13.914 42.061 ;
     RECT  0.108 42.061 13.914 43.469 ;
     RECT  0.144 43.469 13.914 44.38 ;
     RECT  0.108 44.38 13.914 44.525 ;
     RECT  0.144 44.525 13.914 45.532 ;
     RECT  0.108 45.532 13.914 45.677 ;
     RECT  0.144 45.677 13.914 46.157 ;
     RECT  0.468 46.157 13.914 46.987 ;
     RECT  0.108 46.987 13.914 47.501 ;
     RECT  0.144 47.501 13.914 48.361 ;
     RECT  0.108 48.361 13.914 48.695 ;
     RECT  0.108 48.695 8.298 49.981 ;
     RECT  9.18 48.695 13.914 49.981 ;
     RECT  0.108 49.981 13.914 50.279 ;
     RECT  0.108 50.279 8.097 50.285 ;
     RECT  0.144 50.285 8.097 51.601 ;
     RECT  8.892 50.279 13.914 51.971 ;
     RECT  8.892 51.971 10.818 52.007 ;
     RECT  0.144 51.601 8.154 52.061 ;
     RECT  8.892 52.007 10.17 52.349 ;
     RECT  8.892 52.349 9.954 52.619 ;
     RECT  9.9 52.619 9.954 52.781 ;
     RECT  0.144 52.061 8.097 52.972 ;
     RECT  11.988 51.971 13.914 53.429 ;
     RECT  0.108 52.972 8.097 53.564 ;
     RECT  10.8 53.491 10.818 53.591 ;
     RECT  8.892 52.619 8.91 53.789 ;
     RECT  8.964 53.869 8.982 53.969 ;
     RECT  0.144 53.564 8.097 53.981 ;
     RECT  0.144 53.981 7.074 54.029 ;
     RECT  12.06 53.429 13.914 54.059 ;
     RECT  12.564 54.059 13.914 54.437 ;
     RECT  0.324 54.029 7.074 54.715 ;
     RECT  7.815 53.981 8.097 54.715 ;
     RECT  0.324 54.715 8.622 54.763 ;
     RECT  0.288 54.763 8.622 54.841 ;
     RECT  0.288 54.841 8.766 54.955 ;
     RECT  12.564 54.437 13.734 54.977 ;
     RECT  12.564 54.977 13.497 55.013 ;
     RECT  0.216 54.955 8.766 55.099 ;
     RECT  0.144 55.099 8.766 55.139 ;
     RECT  9.9 52.781 9.918 55.139 ;
     RECT  0.144 55.139 8.622 55.211 ;
     RECT  9.54 55.219 9.63 55.255 ;
     RECT  9.36 55.255 9.63 55.409 ;
     RECT  0.144 55.211 8.55 55.589 ;
     RECT  0.144 55.589 0.558 55.805 ;
     RECT  1.692 55.589 8.55 55.949 ;
     RECT  9.468 55.409 9.63 55.949 ;
     RECT  0.18 55.805 0.558 56.333 ;
     RECT  0.288 56.333 0.558 56.381 ;
     RECT  9.648 56.065 9.666 57.029 ;
     RECT  1.692 55.949 8.19 57.137 ;
     RECT  0.504 56.381 0.558 57.259 ;
     RECT  2.16 57.137 8.19 57.379 ;
     RECT  0.324 57.259 0.558 57.403 ;
     RECT  0.216 57.403 0.558 57.479 ;
     RECT  2.16 57.379 8.262 57.649 ;
     RECT  0.216 57.479 0.342 57.691 ;
     RECT  2.16 57.649 8.334 57.839 ;
     RECT  9.756 57.145 9.774 57.839 ;
     RECT  2.16 57.839 8.19 57.875 ;
     RECT  2.16 57.875 8.097 58.019 ;
     RECT  6.48 58.019 8.097 58.067 ;
     RECT  13.215 55.013 13.497 58.067 ;
     RECT  18.615 2.413 18.897 58.067 ;
     RECT  2.304 58.019 5.634 58.109 ;
     RECT  6.48 58.067 7.974 58.109 ;
     RECT  9.792 57.955 9.954 58.109 ;
     RECT  0.18 57.691 0.342 58.123 ;
     RECT  4.392 58.109 5.598 58.157 ;
     RECT  9.792 58.109 9.81 58.157 ;
     RECT  2.304 58.109 3.15 58.181 ;
     RECT  1.152 57.643 1.17 58.205 ;
     RECT  2.304 58.181 2.862 58.217 ;
     RECT  4.968 58.157 5.598 58.217 ;
     RECT  13.215 58.067 13.305 58.337 ;
     RECT  18.615 58.067 18.705 58.337 ;
     RECT  2.304 58.217 2.61 58.379 ;
     RECT  2.592 58.379 2.61 58.397 ;
     RECT  6.516 58.109 7.974 58.445 ;
     RECT  0.108 58.123 0.342 58.523 ;
     RECT  0.18 58.523 0.342 58.541 ;
     RECT  6.516 58.445 7.758 58.637 ;
     RECT  0.18 58.541 0.198 58.685 ;
     RECT  4.968 58.217 5.49 58.685 ;
     RECT  4.968 58.685 5.418 58.829 ;
     RECT  7.344 58.637 7.758 59.117 ;
     RECT  7.344 59.117 7.362 59.213 ;
     RECT  6.516 58.637 6.534 59.309 ;
     RECT  5.4 58.829 5.418 59.405 ;
    LAYER M4 ;
     RECT  0.06 31.536 0.181 59.4 ;
     RECT  0.06 1.296 1.069 29.16 ;
     RECT  0.181 31.44 1.141 59.4 ;
     RECT  1.069 1.296 1.285 29.352 ;
     RECT  1.141 31.344 1.573 59.4 ;
     RECT  1.285 1.296 1.609 29.784 ;
     RECT  1.573 30.864 1.609 59.4 ;
     RECT  1.609 1.296 2.333 59.4 ;
     RECT  2.333 1.392 2.873 59.4 ;
     RECT  2.873 1.488 3.413 59.4 ;
     RECT  3.413 1.584 3.665 59.4 ;
     RECT  3.665 1.968 3.953 59.4 ;
     RECT  3.953 2.352 5.249 59.4 ;
     RECT  5.249 37.056 5.429 59.4 ;
     RECT  5.429 37.056 5.717 59.304 ;
     RECT  5.249 2.352 5.893 36.024 ;
     RECT  5.717 37.056 6.049 41.64 ;
     RECT  5.717 43.008 6.113 59.304 ;
     RECT  6.049 37.296 6.437 41.64 ;
     RECT  6.113 48.192 6.545 59.304 ;
     RECT  6.545 48.192 6.581 59.208 ;
     RECT  6.581 54.96 6.833 59.208 ;
     RECT  6.833 55.008 7.373 59.208 ;
     RECT  7.373 55.008 7.769 59.112 ;
     RECT  5.893 2.256 7.808 36.024 ;
     RECT  6.437 37.296 7.808 40.392 ;
     RECT  6.437 41.616 7.808 41.64 ;
     RECT  6.113 43.008 7.808 47.16 ;
     RECT  6.581 48.192 7.808 53.976 ;
     RECT  7.769 55.008 7.808 58.44 ;
     RECT  7.808 2.148 7.912 58.44 ;
     RECT  7.912 2.256 7.985 58.44 ;
     RECT  7.985 2.256 8.104 58.062 ;
     RECT  8.104 46.032 8.201 47.16 ;
     RECT  8.104 48.192 8.425 55.896 ;
     RECT  8.104 2.256 8.483 30.12 ;
     RECT  8.104 44.064 8.561 45 ;
     RECT  8.104 31.392 8.633 36.024 ;
     RECT  8.425 50.832 8.633 55.896 ;
     RECT  8.633 31.392 8.675 34.968 ;
     RECT  8.633 50.832 8.819 53.928 ;
     RECT  8.201 46.224 8.921 47.16 ;
     RECT  8.104 37.392 8.993 40.392 ;
     RECT  8.483 2.496 9.029 30.12 ;
     RECT  9.029 2.496 9.1 28.92 ;
     RECT  9.1 2.496 9.137 28.728 ;
     RECT  8.561 44.064 9.137 44.472 ;
     RECT  8.819 50.832 9.155 53.88 ;
     RECT  8.993 37.392 9.173 40.152 ;
     RECT  8.921 46.224 9.251 46.776 ;
     RECT  9.155 50.832 9.317 51.384 ;
     RECT  8.675 31.488 9.347 34.968 ;
     RECT  9.137 2.496 9.425 28.68 ;
     RECT  9.425 2.496 9.461 20.328 ;
     RECT  9.425 21.456 9.461 28.68 ;
     RECT  9.347 31.92 9.491 34.968 ;
     RECT  9.461 2.496 9.533 20.04 ;
     RECT  9.461 21.792 9.533 28.68 ;
     RECT  9.533 26.208 9.587 27.384 ;
     RECT  9.587 26.352 9.605 27.384 ;
     RECT  9.397 45.6 9.605 45.624 ;
     RECT  9.533 21.984 9.641 25.224 ;
     RECT  9.533 2.496 9.677 19.32 ;
     RECT  9.677 13.344 9.683 17.64 ;
     RECT  9.533 28.464 9.713 28.68 ;
     RECT  9.173 37.392 9.713 39.048 ;
     RECT  9.137 44.064 9.713 44.136 ;
     RECT  9.677 18.672 9.749 19.32 ;
     RECT  9.641 23.904 9.749 25.224 ;
     RECT  9.713 37.392 9.749 38.712 ;
     RECT  8.104 57.984 9.781 58.008 ;
     RECT  9.677 2.496 9.857 12.264 ;
     RECT  9.605 26.352 9.857 26.808 ;
     RECT  9.683 16.368 9.875 17.64 ;
     RECT  9.857 2.496 9.884 8.808 ;
     RECT  9.857 10.176 9.929 12.264 ;
     RECT  9.641 22.56 9.965 22.584 ;
     RECT  9.884 2.256 9.971 8.808 ;
     RECT  9.781 57.984 9.971 58.152 ;
     RECT  9.749 18.672 10.001 18.744 ;
     RECT  9.749 24.192 10.001 25.224 ;
     RECT  9.929 10.272 10.037 12.264 ;
     RECT  9.857 26.352 10.037 26.76 ;
     RECT  9.029 30.096 10.037 30.12 ;
     RECT  8.633 55.008 10.067 55.896 ;
     RECT  10.001 18.672 10.073 18.696 ;
     RECT  10.037 26.352 10.109 26.712 ;
     RECT  9.971 2.592 10.145 8.808 ;
     RECT  10.109 26.352 10.253 26.664 ;
     RECT  9.683 13.344 10.325 15.384 ;
     RECT  10.001 24.192 10.433 25.032 ;
     RECT  9.173 40.128 10.433 40.152 ;
     RECT  9.155 52.704 10.499 53.88 ;
     RECT  8.104 41.616 10.501 41.64 ;
     RECT  9.875 16.992 10.577 17.64 ;
     RECT  10.253 26.64 10.577 26.664 ;
     RECT  10.145 3.36 10.649 8.808 ;
     RECT  10.325 13.488 10.649 15.384 ;
     RECT  10.649 14.736 10.682 15.384 ;
     RECT  10.649 3.36 10.685 5.352 ;
     RECT  9.251 46.752 10.691 46.776 ;
     RECT  10.685 3.36 10.721 3.384 ;
     RECT  8.425 48.192 10.739 49.608 ;
     RECT  10.682 14.784 10.748 15.384 ;
     RECT  10.577 17.088 10.757 17.64 ;
     RECT  10.649 6.336 10.793 8.808 ;
     RECT  10.037 10.848 10.829 12.264 ;
     RECT  10.748 14.784 10.835 15.672 ;
     RECT  10.739 49.584 10.835 49.608 ;
     RECT  10.757 17.088 10.865 17.544 ;
     RECT  10.829 11.952 10.883 12.264 ;
     RECT  9.971 57.984 10.883 58.008 ;
     RECT  10.793 8.784 10.901 8.808 ;
     RECT  10.865 17.088 10.931 17.112 ;
     RECT  10.501 40.992 10.931 41.64 ;
     RECT  10.892 23.088 10.933 23.112 ;
     RECT  10.685 4.416 10.937 5.352 ;
     RECT  9.491 32.448 10.969 34.968 ;
     RECT  10.793 6.336 10.973 7.176 ;
     RECT  10.933 23.088 10.979 23.4 ;
     RECT  10.979 23.376 11.017 23.4 ;
     RECT  10.937 4.416 11.045 5.016 ;
     RECT  11.045 4.416 11.081 4.92 ;
     RECT  10.973 6.48 11.225 7.176 ;
     RECT  9.749 37.872 11.261 38.712 ;
     RECT  10.835 14.784 11.267 15.384 ;
     RECT  10.739 48.192 11.267 48.504 ;
     RECT  9.713 28.464 11.441 28.488 ;
     RECT  11.225 6.768 11.459 7.176 ;
     RECT  10.499 53.28 11.459 53.88 ;
     RECT  11.267 15.36 11.507 15.384 ;
     RECT  9.317 50.832 11.507 50.856 ;
     RECT  10.969 32.304 11.513 34.968 ;
     RECT  10.649 13.584 11.555 13.608 ;
     RECT  9.713 44.064 11.555 44.088 ;
     RECT  10.883 11.952 11.603 12.072 ;
     RECT  10.931 41.616 11.603 41.64 ;
     RECT  10.829 10.848 12.035 10.872 ;
     RECT  10.067 55.008 12.035 55.032 ;
     RECT  11.261 37.872 12.053 37.896 ;
     RECT  11.081 4.416 13.208 4.44 ;
     RECT  11.459 7.152 13.208 7.176 ;
     RECT  11.603 11.952 13.208 11.976 ;
     RECT  10.433 25.008 13.208 25.032 ;
     RECT  12.265 26.784 13.208 26.808 ;
     RECT  11.513 32.304 13.208 32.904 ;
     RECT  11.513 34.08 13.208 34.968 ;
     RECT  8.633 36 13.208 36.024 ;
     RECT  11.267 48.192 13.208 48.216 ;
     RECT  11.459 53.856 13.208 53.88 ;
     RECT  13.208 2.148 13.312 58.332 ;
     RECT  13.312 2.418 13.504 58.062 ;
     RECT  13.504 7.152 13.781 7.176 ;
     RECT  13.504 11.952 13.817 11.976 ;
     RECT  13.504 26.784 13.961 26.808 ;
     RECT  13.504 32.304 14.069 32.328 ;
     RECT  13.504 34.896 14.609 34.92 ;
     RECT  18.608 2.148 18.712 58.332 ;
     RECT  18.712 2.418 18.904 58.062 ;
    LAYER M5 ;
     RECT  2.4 2.137 2.52 2.151 ;
     RECT  7.8 2.137 7.92 2.151 ;
     RECT  13.2 2.137 13.32 2.151 ;
     RECT  18.6 2.137 18.72 2.151 ;
     RECT  7.8 2.151 8.112 2.245 ;
     RECT  6.288 2.245 6.312 2.915 ;
     RECT  7.296 2.245 8.472 3.301 ;
     RECT  0.144 2.005 0.168 3.635 ;
     RECT  5.136 3.109 5.16 3.683 ;
     RECT  7.248 3.301 8.472 4.117 ;
     RECT  9.936 2.245 9.96 4.117 ;
     RECT  13.2 2.151 13.512 4.405 ;
     RECT  7.248 4.117 9.96 4.499 ;
     RECT  2.4 2.151 2.712 4.933 ;
     RECT  7.248 4.499 9.096 5.317 ;
     RECT  6.672 5.317 9.096 5.461 ;
     RECT  6.672 5.461 9.192 5.603 ;
     RECT  7.248 5.603 9.192 5.797 ;
     RECT  0.144 5.797 0.168 6.083 ;
     RECT  7.248 5.797 9.816 6.229 ;
     RECT  7.248 6.229 10.488 6.757 ;
     RECT  2.16 4.933 2.712 6.997 ;
     RECT  4.944 6.181 4.968 7.237 ;
     RECT  6.24 6.229 6.264 7.381 ;
     RECT  7.248 6.757 11.448 7.381 ;
     RECT  2.16 6.997 3.624 7.621 ;
     RECT  4.944 7.237 5.16 7.621 ;
     RECT  6.24 7.381 11.448 7.763 ;
     RECT  2.16 7.621 5.16 8.245 ;
     RECT  0.144 8.197 0.168 8.819 ;
     RECT  2.064 8.245 5.16 9.301 ;
     RECT  1.68 9.301 5.16 9.925 ;
     RECT  1.68 9.925 5.256 10.117 ;
     RECT  6.288 7.763 11.448 10.117 ;
     RECT  1.104 10.117 11.448 10.165 ;
     RECT  0.528 10.165 11.448 10.837 ;
     RECT  12.528 4.405 13.512 10.837 ;
     RECT  0.528 10.837 13.512 11.605 ;
     RECT  0.144 11.605 13.512 11.987 ;
     RECT  0.528 11.987 13.512 13.333 ;
     RECT  0.432 13.333 13.512 13.861 ;
     RECT  0.144 13.861 13.512 14.051 ;
     RECT  0.24 14.051 13.512 14.195 ;
     RECT  0.432 14.195 13.512 16.357 ;
     RECT  0.144 16.357 13.512 16.547 ;
     RECT  0.432 16.547 13.512 17.509 ;
     RECT  0.24 17.509 13.512 18.421 ;
     RECT  0.144 18.421 13.512 18.803 ;
     RECT  0.432 18.803 13.512 20.245 ;
     RECT  0.144 20.245 13.512 20.435 ;
     RECT  0.432 20.435 13.512 22.501 ;
     RECT  0.144 22.501 13.512 24.467 ;
     RECT  0.432 24.467 13.512 31.429 ;
     RECT  0.192 31.429 13.512 32.339 ;
     RECT  0.432 32.339 13.512 38.965 ;
     RECT  0.192 38.965 13.512 39.779 ;
     RECT  0.432 39.779 13.512 45.781 ;
     RECT  0.144 45.781 13.512 46.067 ;
     RECT  0.432 46.067 13.512 47.653 ;
     RECT  0.144 47.653 13.512 47.843 ;
     RECT  0.432 47.843 13.512 48.227 ;
     RECT  0.432 48.227 12.024 51.971 ;
     RECT  9.84 51.971 12.024 53.315 ;
     RECT  0.432 51.971 8.808 53.939 ;
     RECT  0.432 53.939 8.232 54.421 ;
     RECT  0.144 54.421 8.232 54.707 ;
     RECT  0.192 54.707 8.232 54.755 ;
     RECT  12 53.315 12.024 55.043 ;
     RECT  0.192 54.755 8.112 55.187 ;
     RECT  0.432 55.187 8.112 55.331 ;
     RECT  0.432 55.331 6.792 55.523 ;
     RECT  9.84 53.315 10.872 55.907 ;
     RECT  0.48 55.523 6.792 56.483 ;
     RECT  5.808 56.483 6.792 56.533 ;
     RECT  7.8 55.331 8.112 56.533 ;
     RECT  5.808 56.533 8.112 56.723 ;
     RECT  0.48 56.483 4.536 57.059 ;
     RECT  5.808 56.723 6.792 57.059 ;
     RECT  1.632 57.059 4.536 57.107 ;
     RECT  0.48 57.059 0.552 57.109 ;
     RECT  0.144 57.109 0.552 57.347 ;
     RECT  0.144 57.347 0.504 57.395 ;
     RECT  0.48 57.395 0.504 57.587 ;
     RECT  1.632 57.107 3.96 57.635 ;
     RECT  6.768 57.059 6.792 57.635 ;
     RECT  1.632 57.635 2.808 57.683 ;
     RECT  3.936 57.635 3.96 57.875 ;
     RECT  10.848 55.907 10.872 58.019 ;
     RECT  9.84 55.907 9.864 58.117 ;
     RECT  2.4 57.683 2.808 58.163 ;
     RECT  2.4 58.163 2.712 58.329 ;
     RECT  7.8 56.723 8.112 58.329 ;
     RECT  13.2 48.227 13.512 58.329 ;
     RECT  18.6 2.151 18.912 58.329 ;
     RECT  2.4 58.329 2.52 58.343 ;
     RECT  7.8 58.329 7.92 58.343 ;
     RECT  13.2 58.329 13.32 58.343 ;
     RECT  18.6 58.329 18.72 58.343 ;
     RECT  9.84 58.117 9.96 60.432 ;
  END
END dsfd_rly_283_WW
END LIBRARY
